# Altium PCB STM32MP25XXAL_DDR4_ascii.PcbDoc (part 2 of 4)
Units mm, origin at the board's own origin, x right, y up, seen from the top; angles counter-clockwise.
Board outline 125 x 95 mm, 6 copper layers (Top Layer, Signal Layer 1, Signal Layer 2, Signal Layer 3, Signal Layer 4, Bottom Layer), stack 1.403 mm thick; 220 components, 316 nets, 1103 pads, 939 vias.
Unrouted connection lines stored in the file: 5.

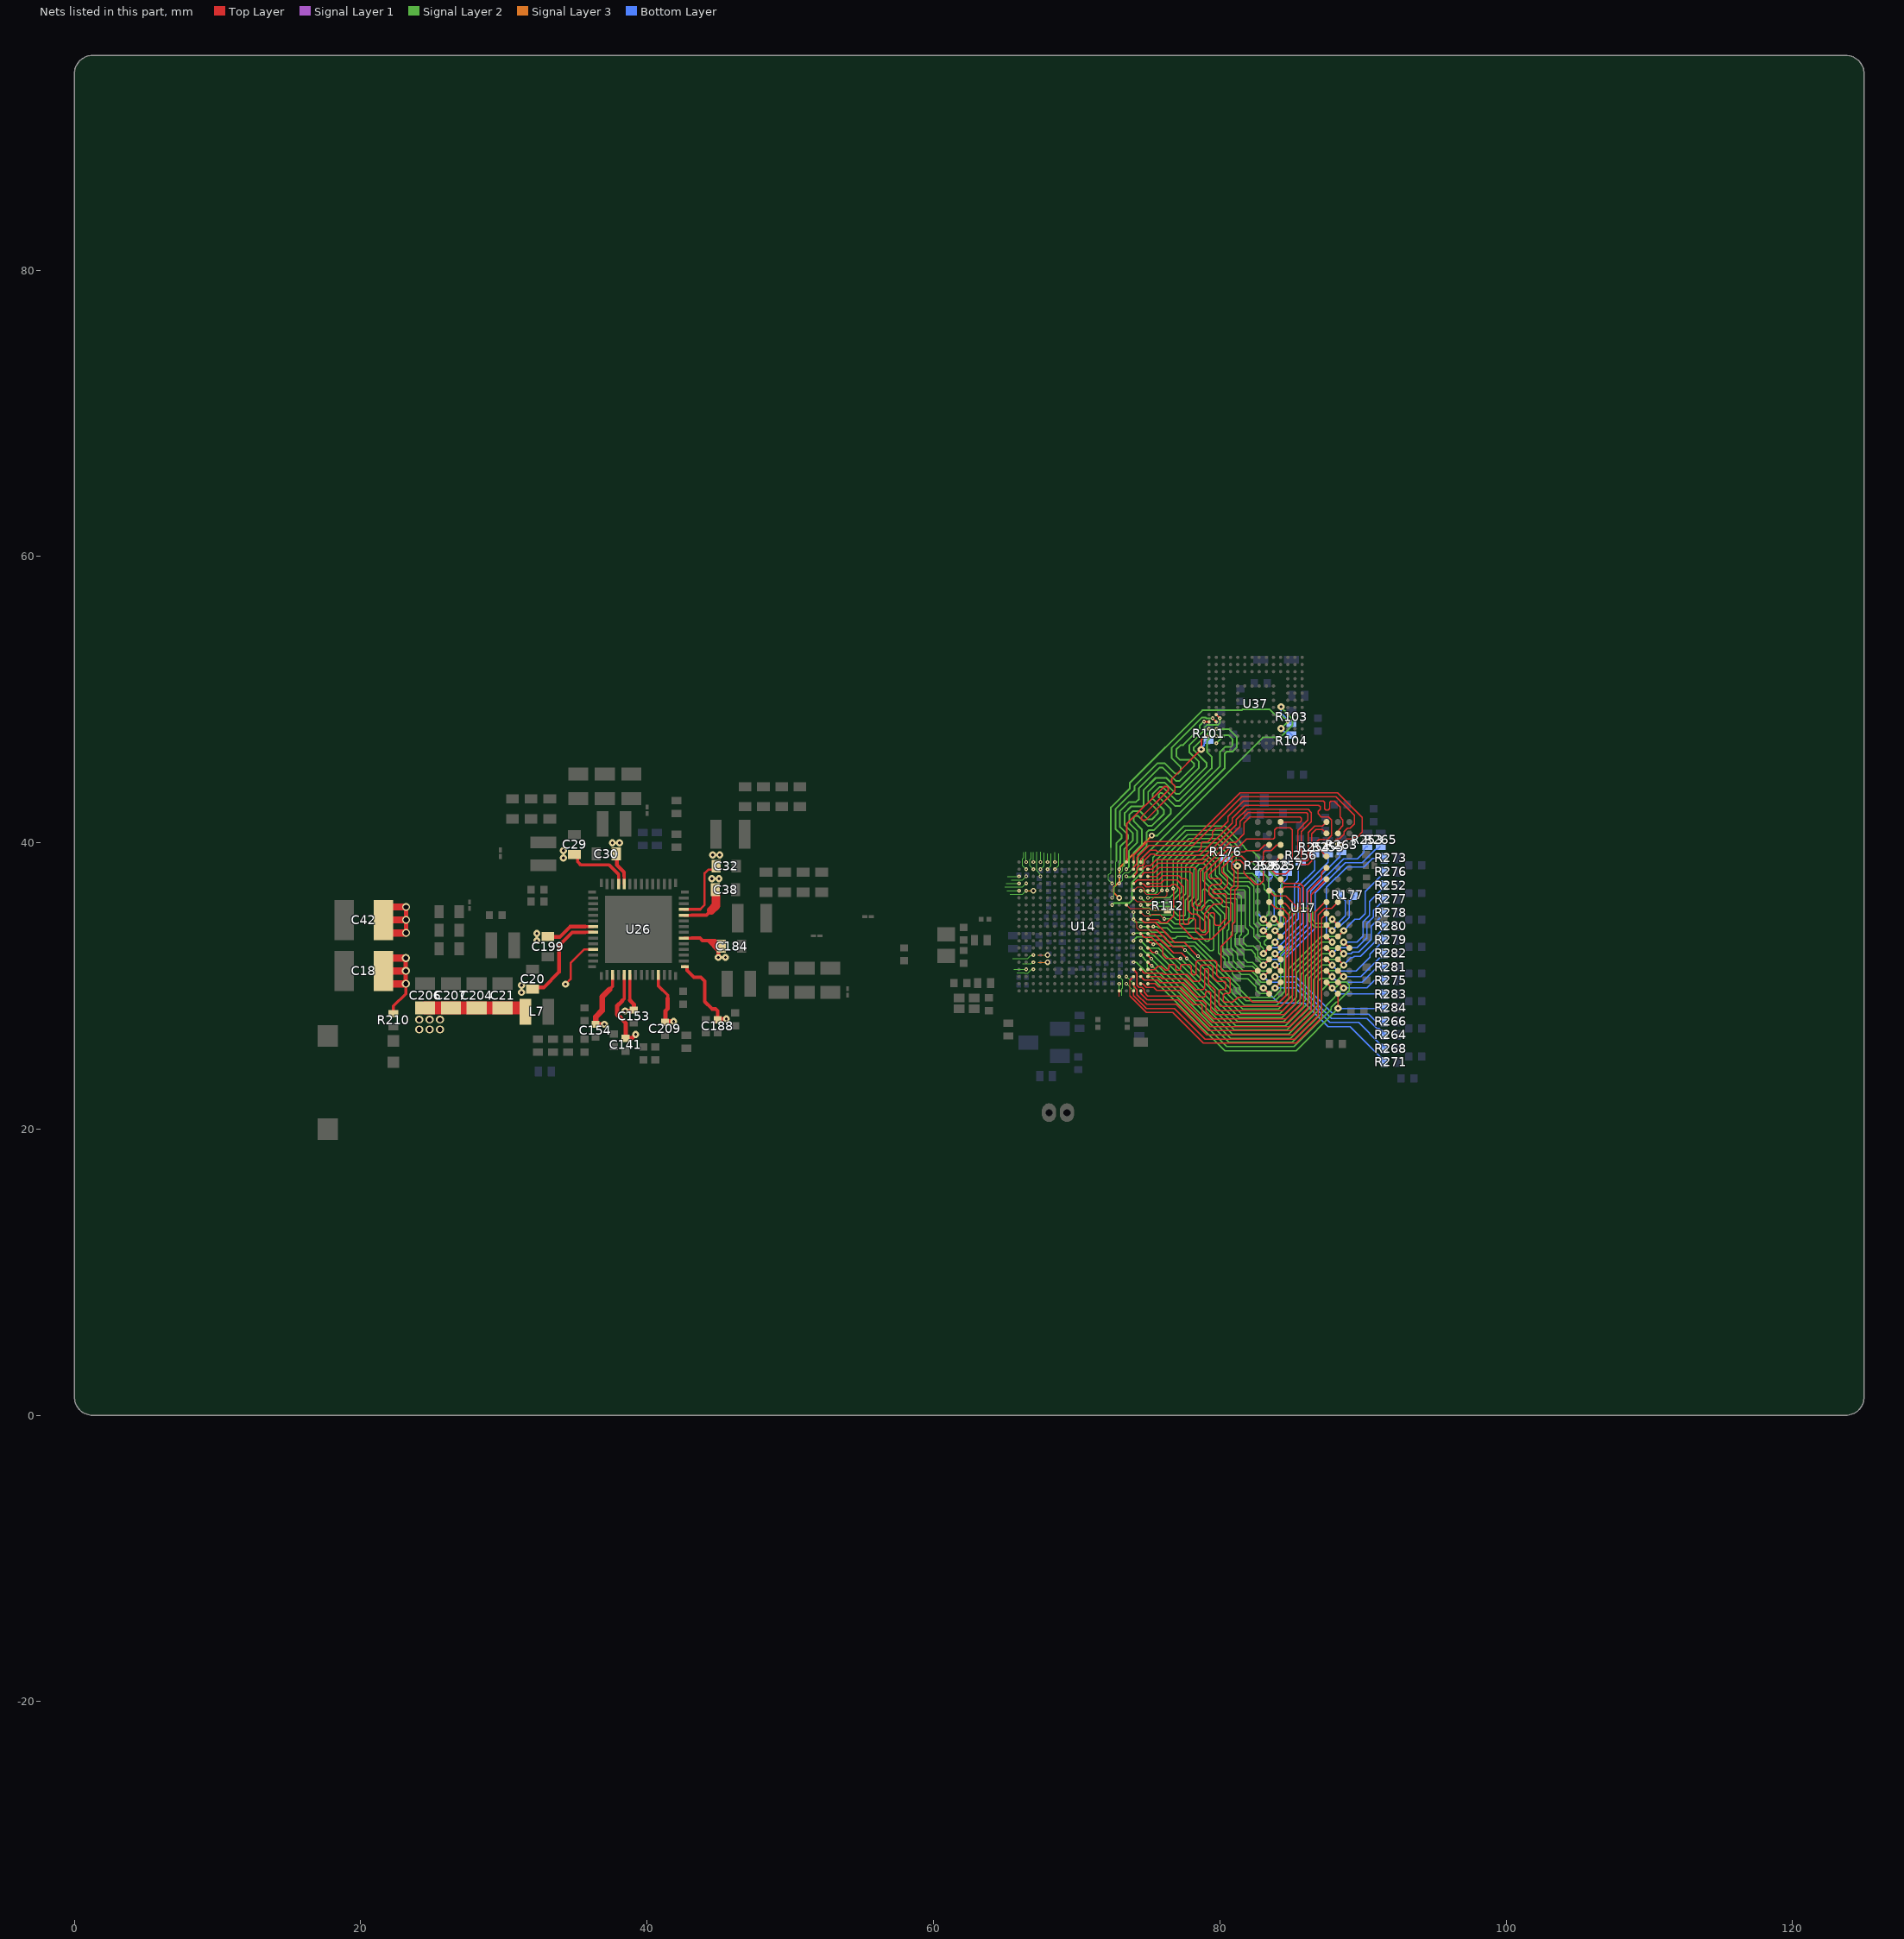
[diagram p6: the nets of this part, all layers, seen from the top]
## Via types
v1: diameter 0.5, hole 0.2, Top Layer to Bottom Layer, 292 vias
v2: diameter 0.26, hole 0.1, Top Layer to Signal Layer 1, 266 vias
v3: diameter 0.26, hole 0.1, Signal Layer 1 to Signal Layer 2, 143 vias
v4: diameter 0.4, hole 0.2, Signal Layer 1 to Signal Layer 4, 101 vias
v5: diameter 0.26, hole 0.1, Signal Layer 4 to Bottom Layer, 81 vias
v6: diameter 0.55, hole 0.35, Top Layer to Bottom Layer, 55 vias
v7: diameter 0.5, hole 0.2, Signal Layer 1 to Signal Layer 4, 1 vias

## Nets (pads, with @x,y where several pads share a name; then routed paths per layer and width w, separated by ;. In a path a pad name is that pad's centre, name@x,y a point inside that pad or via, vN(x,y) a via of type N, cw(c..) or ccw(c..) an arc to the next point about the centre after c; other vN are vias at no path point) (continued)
3V3: C21.2 C154.2 C204.2 C206.2 C207.2 L7.2 U26.3 U26.53 | length 15.3
  Top Layer w0.15: v1(34.308,30.116) 34.66,30.468 34.66,31.604 35.595,32.539 U26.53@36.228,32.539 ; U26.53@36.018,32.508 36.317,32.508 U26.53@36.348,32.539
  Top Layer w0.21: 37.371,29.736 37.598,29.964 U26.3@37.598,30.769
  Top Layer w0.3: C154.2@36.373,27.314 C154.2@36.398,27.314 v1@36.983,27.314
  Top Layer w0.4: C154.2@36.398,27.314 36.412,27.328 36.412,27.824 36.858,28.27 36.858,29.224 37.371,29.736
  Top Layer w0.9: C206.2@24.485,28.462 C21.2@29.898,28.462 31.26,28.462 L7.2@31.285,28.437
  other v1: 37.008,27.314
  other v6: 24.085,26.962 24.81,26.962 25.535,26.962 24.085,27.637 24.81,27.637 25.535,27.637
5V_STLK: C18.1 C20.2 C29.2 C30.2 C32.2 C38.2 C42.1 C153.2 C184.2 C188.2 C199.2 C209.2 R210.1 U26.6 U26.11 U26.15 U26.20 U26.24 U26.25 U26.38 U26.39 U26.49 U26.50 | length 58.9
  Top Layer w0.15: 43.698,35.339 44.023,35.664 44.023,37.87 44.286,38.133 44.717,38.133 C32.2@44.823,38.239
  Top Layer w0.2: R210.1@22.284,28.054 22.284,28.588 23.142,29.446 v6@23.142,30.133
  Top Layer w0.21: C29.2@34.923,39.189 35.16,38.952 35.16,38.652 35.373,38.439 37.362,38.439 37.998,37.803 U26.39@37.998,37.109 ; 35.673,33.739 U26.50@36.228,33.739 ; 35.673,34.139 U26.49@36.228,34.139 ; U26.38@38.398,37.109 38.398,37.664 ; 38.798,28.989 U26.6@38.798,30.769 ; U26.11@40.798,30.769 40.798,29.982 41.438,29.342 41.438,29.114 ; U26.15@42.568,31.339 U26.15@42.643,31.339 U26.15@42.683,31.339 ; U26.20@42.568,33.339 43.123,33.339 ; U26.24@42.568,34.939 43.105,34.939 ; U26.25@42.568,35.339 43.698,35.339
  Top Layer w0.25: C20.2@31.998,29.889 32.773,29.889 33.848,30.964 33.848,32.808 34.779,33.739 35.673,33.739 ; C199.2@33.073,33.414 33.889,33.414 34.614,34.139 35.673,34.139 ; C30.2@37.823,39.214 37.892,39.145 37.892,38.447 38.398,37.941 38.398,37.664 ; 42.793,31.234 42.793,31.086 43.269,30.611 43.751,30.611 44.023,30.339 44.023,28.898 44.532,28.389 44.777,28.389 44.923,28.243 C188.2@44.923,27.689 ; 43.105,34.939 44.148,34.939 44.473,35.264 ; 43.123,33.339 43.686,33.339 43.861,33.164 44.256,33.164 ; v1(44.973,31.989) 44.973,32.447 44.256,33.164 ; 44.256,33.164 44.477,33.164 ; 44.477,33.164 44.875,32.766 45.144,32.766 45.145,32.764 45.145,32.842 44.948,33.039 44.87,33.039 44.745,33.164 44.477,33.164
  Top Layer w0.3: v6@23.148,30.139 23.148,31.045 v6@23.148,31.939 ; v6@23.173,33.702 v6@23.173,35.502 ; v1(38.463,28.249) 39.073,28.249 39.072,28.25 39.072,28.715 38.798,28.989 ; C209.2@41.248,27.519 C209.2@41.273,27.519 ; 41.438,29.114 41.438,28.408 41.273,28.243 C209.2@41.273,27.519 ; v1(41.858,27.519) C209.2@41.273,27.519 ; C188.2@44.923,27.689 v1(45.533,27.689)
  Top Layer w0.5: C18.1@21.584,30.133 23.142,30.133 v6@23.167,30.133 ; C18.1@21.584,31.045 23.148,31.045 v6@23.167,31.045 ; C18.1@21.584,31.945 v6@23.167,31.945 ; C42.1@21.584,33.696 v6@23.167,33.696 ; C42.1@21.584,34.607 v6@23.167,34.607 ; C42.1@21.584,35.507 v6@23.167,35.507
  Top Layer w0.6: 44.473,35.264 44.798,35.589 C38.2@44.798,36.314
  other v1: 31.223,29.539 31.223,30.039 45.473,31.989 32.298,33.164 32.298,33.664 44.523,37.489 45.023,37.489 34.148,38.939 44.573,39.139 45.073,39.139 34.148,39.439 37.573,39.989 38.073,39.989
  other v6: 23.149,30.141 23.149,31.041 23.149,31.941 23.174,33.704 23.174,34.604 23.174,35.504
5V_VCONN: C141.1 U26.5 | length 5.7
  Top Layer w0.21: 38.276,28.966 38.398,29.089 U26.5@38.398,30.769
  Top Layer w0.3: 38.276,28.966 37.908,28.599 37.908,28.004 38.498,27.414 C141.1@38.498,26.339 38.938,26.339 v1(39.198,26.599)
ANA0: U14.R5 | length 0.7
  Signal Layer 3 w0.075: 67.3,31.65 v4(67.975,31.65)
  other v2: 67.975,31.65
ANA1: U14.P5 | length 0.7
  Signal Layer 3 w0.075: 67.275,32.15 v4(67.975,32.15)
  other v2: 67.975,32.15
BOOT0: U14.T2 | length 0.9
  Signal Layer 2 w0.075: 65.625,31.15 v3(66.475,31.15)
  other v2: 66.475,31.15
BOOT1: U14.P3 | length 1.6
  Signal Layer 2 w0.075: 65.526,31.901 66.578,31.901 66.612,31.934 66.613,31.934 66.806,32.126 66.951,32.126 v3(66.975,32.15)
  other v2: 66.975,32.15
BOOT2: U14.T3 | length 1.3
  Signal Layer 2 w0.075: 65.822,30.925 66.347,30.925 66.372,30.901 66.578,30.901 66.724,31.047 66.724,31.05 66.804,31.129 66.954,31.129 v3(66.975,31.15)
  other v2: 66.975,31.15
BOOT3: U14.R3 | length 0.8
  Signal Layer 2 w0.075: 66.221,31.558 66.839,31.558 66.931,31.65 v3(66.975,31.65)
  other v2: 66.975,31.65
COMBOPHY_REXT: U14.W15 | length 0.4
  Top Layer w0.075: 72.975,29.25 U14.W15@72.975,29.65
COMBOPHY_RX1N: U14.V16 | length 0.5
  Signal Layer 2 w0.075: v3(73.475,30.15) 73.819,29.806 73.819,29.763
  other v2: 73.475,30.15
COMBOPHY_RX1P: U14.U16 | length 1.3
  Signal Layer 2 w0.075: v3(73.475,30.65) 74.017,30.108 74.017,29.617
  other v2: 73.475,30.65
COMBOPHY_TX1N: U14.V15 | length 0.8
  Signal Layer 2 w0.075: 72.975,29.325 v3(72.975,30.15)
  other v2: 72.975,30.15
COMBOPHY_TX1P: U14.U15 | length 1.5
  Signal Layer 2 w0.075: v3(72.975,30.65) 73.224,30.401 73.224,29.874 73.15,29.8 73.15,29.325
  other v2: 72.975,30.65
CSI_CKN: U14.C2 | length 1.2
  Signal Layer 2 w0.075: 65.425,37.4 65.426,37.399 66.224,37.399 v3(66.475,37.65)
  other v2: 66.475,37.65
CSI_CKP: U14.C1 | length 0.8
  Signal Layer 2 w0.075: 65.175,37.65 65.973,37.65 v3(65.975,37.648)
  other v2: 65.975,37.648
CSI_D0N: U14.E1 | length 0.8
  Signal Layer 2 w0.075: 65.15,36.65 v3(65.975,36.65)
  other v2: 65.975,36.65
CSI_D0P: U14.E2 | length 1.2
  Signal Layer 2 w0.075: 65.35,36.4 66.225,36.4 v3(66.475,36.65)
  other v2: 66.475,36.65
CSI_D1N: U14.D2 | length 1.6
  Signal Layer 2 w0.075: 64.982,36.9 66.225,36.9 v3(66.475,37.15)
  other v2: 66.475,37.15
CSI_D1P: U14.D1 | length 0.9
  Signal Layer 2 w0.075: 65.076,37.149 v3(65.975,37.149)
  other v2: 65.975,37.149
CSI_REXT: U14.E3 | length 0.6
  Signal Layer 3 w0.075: 66.4,36.65 v2(66.975,36.65)
  other v4: 66.975,36.65
DDR_A0: R265.1 U14.H19 U17.P3 | length 31.3
  Top Layer w0.09: v1@83.855,31.445 U17.P3@84.25,31.05
  Signal Layer 2 w0.09: v3(74.975,35.15) 75.159,34.966 76.619,34.966 76.975,34.61 77.705,34.61 77.866,34.771 77.866,35.871 78.199,36.204 78.199,38.158 78.586,38.545 78.894,38.545 79.104,38.335 79.104,37.485 80.479,36.11 81.107,36.11 81.205,36.012 81.205,33.714 81.083,33.592 81.083,32.782 81.683,32.181 ; 81.683,32.18 81.683,31.891 81.924,31.65 82.291,31.65 82.891,31.05 83.446,31.05 v1@83.846,31.45
  Bottom Layer w0.09: v1@83.875,31.45 83.953,31.528 84.153,31.528 86.655,34.03 86.655,36.49 88.756,38.591 89.936,38.591 90.89,39.545 91,39.545 R265.1@91.21,39.755
  other v1: 83.85,31.45
  other v2: 74.975,35.15
DDR_A1: R281.1 U14.N18 U17.P7 | length 23.4
  Top Layer w0.09: U17.P7@87.45,31.05 v1(87.85,30.65)
  Signal Layer 2 w0.09: v3(74.475,32.65) 74.83,32.295 75.22,32.295 80.88,26.635 81.175,26.635 84.83,26.635 86.829,28.633 86.829,30.323 87.041,30.535 87.624,30.535 87.739,30.65 v1(87.85,30.65)
  Bottom Layer w0.09: v1(87.85,30.65) 88.255,30.245 89.945,30.245 90.973,31.273 91.448,31.273 R281.1@91.5,31.325
  other v2: 74.475,32.65
DDR_A2: R268.1 U14.K18 U17.R3 | length 28.8
  Top Layer w0.09: v1@83.848,29.852 84.246,30.25 U17.R3@84.25,30.25
  Signal Layer 2 w0.09: v3(74.475,34.15) 74.84,34.15 75.232,33.758 76.186,33.758 76.604,33.34 76.89,33.34 77,33.45 77.713,33.45 77.823,33.34 78.4,33.34 79.295,32.445 79.486,32.445 79.584,32.543 79.584,34.715 79.026,35.274 79.026,35.391 79.226,35.591 79.358,35.591 80.045,34.904 80.045,34.194 79.923,34.072 79.923,32.301 80.35,31.873 80.35,31.534 80.885,30.999 80.885,30.855 81.24,30.5 81.949,30.5 82.525,29.924 82.525,29.7 82.77,29.455 83.448,29.455 83.843,29.85 v1(83.85,29.85)
  Bottom Layer w0.09: v1(83.85,29.85) 85.271,29.85 87.561,27.561 87.676,27.445 89.705,27.445 91.225,25.925 91.275,25.925 91.55,25.65 R268.1@91.55,25.6
  other v2: 74.475,34.15
DDR_A3: R279.1 U14.M18 U17.N7 | length 24.1
  Top Layer w0.09: U17.N7@87.45,31.85 v1(87.85,31.45)
  Signal Layer 2 w0.09: v3(74.475,33.15) 75.002,32.623 75.715,32.623 81.122,27.215 84.588,27.215 86.249,28.876 86.249,30.563 87.135,31.45 v1(87.85,31.45)
  Bottom Layer w0.09: v1(87.85,31.45) 88.252,31.048 89.532,31.048 90.477,31.993 90.477,32.202 91.19,32.915 91.275,32.915 91.525,33.165 R279.1@91.525,33.25
  other v2: 74.475,33.15
DDR_A4: R263.1 U14.G19 U17.N3 | length 28
  Top Layer w0.09: U14.G19@74.975,35.65 74.979,35.646 75.387,35.646 v2@75.508,35.525 ; v1(83.85,32.25) 83.85,32.246 U17.N3@84.253,31.843
  Signal Layer 2 w0.09: v3@75.623,35.548 76.856,35.548 76.93,35.475 77.2,35.475 77.286,35.561 77.286,36.111 77.619,36.445 77.619,38.398 78.346,39.125 79.135,39.125 79.684,38.576 79.684,37.726 80.72,36.69 81.676,36.69 81.785,36.581 81.785,34.08 81.983,33.882 81.983,33.672 81.663,33.351 81.663,33.024 81.894,32.793 82.357,32.793 82.653,32.497 82.653,32.096 ; 82.655,32.094 82.9,31.85 83.45,31.85 ; 83.455,31.855 v1(83.85,32.25)
  Bottom Layer w0.09: v1@83.784,32.192 v1@83.846,32.254 ; v1(83.85,32.25) 83.928,32.328 84.133,32.328 86.075,34.27 86.075,36.73 88.382,39.038 88.382,39.232 R263.1@88.525,39.375
  other v2: 75.525,35.531
  other v3: 75.525,35.531
DDR_A5: R282.1 U14.P19 U17.P8 | length 22.8
  Top Layer w0.09: U14.P19@74.975,32.15 v2@75.275,31.85 ; U17.P8@88.25,31.05 v1(88.65,30.65)
  Signal Layer 2 w0.09: v3@75.21,31.885 80.75,26.345 80.931,26.345 84.95,26.345 87.119,28.513 87.119,29.687 87.682,30.25 88.072,30.25 88.393,30.572 88.572,30.572 v1(88.65,30.65)
  Bottom Layer w0.09: v1(88.65,30.65) 89.85,30.65 91.17,31.97 91.275,31.97 91.5,32.195 R282.1@91.5,32.3
  other v2: 75.22,31.895
  other v3: 75.22,31.895
DDR_A6: R264.1 U14.H18 U17.P2 | length 28.9
  Top Layer w0.075: U14.H18@74.475,35.15 74.725,34.9 75.175,34.9 75.3,35.025 75.781,35.025 v3(76.125,34.682)
  Top Layer w0.09: v1(83.05,30.65) U17.P2@83.45,31.05
  Signal Layer 2 w0.09: v3@76.131,34.676 76.498,34.676 76.854,34.32 77.825,34.32 78.156,34.651 78.156,35.751 78.489,36.084 78.489,38.038 78.624,38.173 78.739,38.173 78.814,38.097 78.814,37.365 80.359,35.82 80.795,35.82 80.915,35.7 80.915,33.834 80.793,33.712 80.793,32.662 81.221,32.233 81.221,31.894 81.745,31.37 82.282,31.37 v1@83.042,30.61 ; v1@83.042,30.65 v1(83.05,30.65)
  Bottom Layer w0.09: v1(83.05,30.65) 83.455,30.245 85.286,30.245 87.603,27.928 87.796,27.735 90.28,27.735 90.98,27.035 91.123,27.035 91.275,26.883 91.275,26.825 R264.1@91.525,26.575
  other v2: 76.125,34.682
DDR_A7: R275.1 U14.R19 U17.R8 | length 21.2
  Top Layer w0.09: U14.R19@74.975,31.65 v2@75.2,31.425 ; U17.R8@88.25,30.25 v1(88.65,29.85)
  Signal Layer 2 w0.09: v3(75.25,31.4) 75.275,31.4 80.62,26.055 85.07,26.055 87.409,28.393 87.409,28.609 v1(88.65,29.85)
  Bottom Layer w0.09: v1(88.65,29.85) 90.275,29.85 90.8,30.375 R275.1@91.475,30.375
  other v2: 75.25,31.4
DDR_A8: R266.1 U14.H17 U17.R2 | length 28.9
  Top Layer w0.09: U17.R2@83.45,30.25 v1(83.85,30.65)
  Signal Layer 2 w0.09: v3(73.975,35.15) 73.975,34.55 74.085,34.44 75.723,34.44 75.825,34.338 76.426,34.338 76.734,34.03 78.53,34.03 78.816,33.744 78.933,33.744 79.004,33.815 79.004,34.471 78.446,35.029 78.446,35.631 78.779,35.964 78.779,36.679 78.875,36.775 78.994,36.775 80.239,35.53 80.522,35.53 80.625,35.427 80.625,33.954 80.503,33.832 80.503,32.541 80.931,32.113 80.931,31.773 81.625,31.08 82.205,31.08 82.655,30.63 82.655,30.48 82.88,30.255 83.48,30.255 v1@83.875,30.65
  Bottom Layer w0.09: v1(83.85,30.65) 85.291,30.65 87.916,28.025 90.4,28.025 90.9,27.525 R266.1@91.55,27.525
  other v2: 73.975,35.15
DDR_A9: R283.1 U14.P18 U17.R7 | length 25.4
  Top Layer w0.09: U17.R7@87.45,30.25 v1(87.85,29.85)
  Signal Layer 2 w0.09: v3@74.475,32.144 74.935,31.684 74.935,31.305 80.475,25.765 85.191,25.765 87.775,28.349 87.775,28.509 88.141,28.875 88.239,28.875 89.045,29.681 89.045,30.055 88.85,30.25 88.491,30.25 88.15,29.909 87.909,29.909 v1(87.85,29.85)
  Bottom Layer w0.09: v1(87.85,29.85) 88.275,29.425 R283.1@91.525,29.425
  other v2: 74.475,32.15
  other v3: 74.475,32.15
DDR_A10: R254.1 U14.F19 U17.M3 | length 25.6
  Top Layer w0.09: v1@83.85,33.049 U17.M3@84.25,32.65
  Signal Layer 2 w0.09: v3@74.974,36.15 76.504,36.15 77.039,36.685 77.039,38.638 78.106,39.705 79.68,39.705 79.768,39.616 79.768,39.312 79.86,39.219 80.165,39.219 80.264,39.121 80.264,37.966 80.96,37.27 82.053,37.27 82.365,36.958 82.365,34.366 82.655,34.076 82.655,33.58 82.785,33.45 83.2,33.45 83.275,33.375 83.275,33.253 83.114,33.093 83.114,32.946 83.364,32.696 83.496,32.696 v1(83.85,33.05)
  Bottom Layer w0.09: v1(83.85,33.05) 85.495,34.695 85.495,36.971 86.625,38.1 86.625,39.2 R254.1@86.6,39.225
  other v2: 74.975,36.15
  other v3: 74.975,36.15
DDR_A11: R271.1 U14.K19 U17.T2 | length 27.5
  Top Layer w0.075: U14.K19@74.975,34.15 v2(75.35,34.15)
  Top Layer w0.09: v1@83.071,29.84 83.45,29.461 U17.T2@83.45,29.45
  Signal Layer 2 w0.09: v2(75.35,34.15) 75.603,34.15 75.705,34.048 76.306,34.048 76.614,33.74 78.41,33.74 79.024,33.126 79.189,33.126 79.294,33.231 79.294,34.595 78.736,35.153 78.736,35.511 79.213,35.988 79.371,35.988 80.335,35.024 80.335,34.074 80.213,33.952 80.213,32.421 80.64,31.994 80.64,31.654 81.505,30.79 82.069,30.79 83.025,29.834 v1@83.025,29.8 ; v1@83.025,29.85 v1(83.05,29.85)
  Bottom Layer w0.09: v1(83.05,29.85) 84.1,28.8 85.911,28.8 87.556,27.155 89.109,27.155 91.275,24.99 91.275,24.9 R271.1@91.5,24.675
  other v3: 75.35,34.15
DDR_A12: R277.1 U14.L18 U17.M7 | length 25.6
  Top Layer w0.09: U14.L18@74.475,33.65 74.725,33.4 75.241,33.4 76.025,32.616 ; 76.025,32.625 76.025,32.616 ; v3(77.255,31.917) 76.258,31.917 76.025,32.15 76.025,32.616 ; U17.M7@87.45,32.65 v1(87.85,32.25)
  Signal Layer 2 w0.09: v3(77.255,31.917) 77.255,31.902 81.362,27.795 84.348,27.795 85.669,29.116 85.669,30.804 87.115,32.25 v1(87.85,32.25)
  Bottom Layer w0.09: v1@87.85,32.25 88.255,32.655 89.59,32.655 90.29,33.355 90.29,34.341 90.74,34.792 90.74,35.265 91.24,35.765 91.275,35.765 91.525,36.015 R277.1@91.525,36.05
  other v2: 77.255,31.917
DDR_A13: R284.1 U14.R17 U17.T8 | length 22.4
  Top Layer w0.09: v1(88.25,28.425) U17.T8@88.25,29.45
  Signal Layer 2 w0.09: v3@73.925,31.65 v3(73.975,31.65) 74.18,31.65 80.355,25.475 85.325,25.475 88.25,28.4 v1(88.25,28.425)
  Bottom Layer w0.09: v1(88.25,28.425) 91.5,28.425 R284.1@91.525,28.45
  other v2: 73.975,31.65
DDR_ACTN: R256.1 U14.E19 U17.L3 | length 24.4
  Top Layer w0.09: U14.E19@74.975,36.65 75,36.675 v2(75.325,36.675) ; v1(83.85,33.85) U17.L3@84.25,33.45
  Signal Layer 2 w0.09: v3@75.325,36.65 75.325,38.975 77.505,41.155 80.35,41.155 81.427,40.077 81.427,40.008 81.714,39.721 81.714,39.668 81.931,39.45 82.259,39.45 82.75,38.959 82.75,38.775 ; 82.757,38.761 84.325,37.193 84.325,35.57 84.468,35.427 84.468,34.403 83.915,33.85 v1(83.85,33.85)
  Bottom Layer w0.09: v1(83.85,33.85) 83.961,33.85 84.071,33.96 84.136,33.96 85.205,35.029 85.205,37.091 85.47,37.355 85.47,38.52 R256.1@85.65,38.7
  other v3: 75.325,36.675
DDR_BA0: R253.1 U14.G18 U17.N2 | length 30.9
  Top Layer w0.09: v1@83.052,31.447 83.45,31.845 U17.N2@83.45,31.85
  Signal Layer 2 w0.09: v3(74.475,35.65) 74.685,35.44 75.095,35.44 75.279,35.256 76.739,35.256 77.095,34.9 77.523,34.9 77.576,34.953 77.576,35.991 77.909,36.324 77.909,38.278 78.466,38.835 79.014,38.835 79.394,38.456 79.394,37.606 80.599,36.4 81.335,36.4 81.495,36.24 81.495,33.594 81.373,33.471 81.373,32.902 81.772,32.503 82.189,32.503 82.473,32.219 82.473,32.022 83.045,31.45 v1(83.05,31.45)
  Bottom Layer w0.09: v1(83.05,31.45) 83.455,31.855 84.07,31.855 86.365,34.15 86.365,36.61 88.635,38.881 89.604,38.881 90.051,39.328 90.051,39.545 90.231,39.725 R253.1@90.325,39.725
  other v2: 74.475,35.65
DDR_BA1: R280.1 U14.N19 U17.N8 | length 23.7
  Top Layer w0.09: U14.N19@74.975,32.65 74.989,32.65 75.296,32.343 v2(75.584,32.343) ; U17.N8@88.25,31.85 v1(88.65,31.45) v1@88.62,31.45
  Signal Layer 2 w0.09: v2(75.584,32.343) 81.002,26.925 84.71,26.925 86.539,28.753 86.539,30.443 87.148,31.053 88.253,31.053 v1(88.65,31.45)
  Bottom Layer w0.09: v1(88.65,31.45) 89.16,31.96 89.295,31.96 89.41,32.075 89.83,32.075 90.87,33.115 90.87,33.46 91.525,34.115 R280.1@91.525,34.175
  other v3: 75.584,32.343
DDR_BG0: R255.1 U14.F18 U17.M2 | length 26.9
  Top Layer w0.09: v1@83.058,32.258 83.058,32.27 83.438,32.65 U17.M2@83.45,32.65
  Signal Layer 2 w0.09: v3(74.475,36.15) 74.895,35.73 75.195,35.73 75.303,35.838 76.603,35.838 77.329,36.565 77.329,38.518 78.226,39.415 79.255,39.415 79.74,38.929 79.87,38.929 79.974,38.826 79.974,37.846 80.84,36.98 81.932,36.98 82.075,36.837 82.075,34.246 82.365,33.956 82.365,33.46 82.824,33.001 82.824,32.826 83.05,32.6 v1(83.05,32.258) v1@83.05,32.225
  Bottom Layer w0.09: v1(83.05,32.258) 83.448,32.655 84.05,32.655 85.785,34.39 85.785,36.85 87.575,38.64 R255.1@87.575,39.225
  other v2: 74.475,36.15
DDR_BG1: R252.1 U14.L19 U17.M9 | length 25.3
  Top Layer w0.09: U14.L19@74.981,33.644 75.426,33.644 76.764,32.306 77.319,32.306 v2@77.7,31.925 ; v1(88.65,33.05) U17.M9@89.05,32.65
  Signal Layer 2 w0.09: v2(77.695,31.92) 80.27,29.345 80.27,29.298 81.482,28.085 84.228,28.085 85.379,29.236 85.379,30.924 87.103,32.648 88.248,32.648 v1(88.65,33.05)
  Bottom Layer w0.09: v1(88.65,33.05) 89.575,33.05 90,33.475 90,34.461 90.45,34.912 90.45,35.89 91.5,36.94 R252.1@91.5,37.025
  other v3: 77.695,31.92
DDR_CASN: R278.1 U14.M19 U17.M8 | length 24.2
  Top Layer w0.09: U14.M19@74.975,33.15 75.102,33.023 75.212,33.023 75.335,32.9 v3(75.35,32.9) ; U17.M8@88.25,32.65 v1(88.65,32.25)
  Signal Layer 2 w0.09: v3(75.35,32.9) 75.373,32.923 75.824,32.923 81.242,27.505 84.468,27.505 85.959,28.996 85.959,30.683 87.125,31.85 88.25,31.85 v1(88.65,32.25)
  Bottom Layer w0.09: v1(88.65,32.25) 89.175,32.25 89.29,32.365 89.71,32.365 90.58,33.235 90.58,34.162 91.233,34.815 91.275,34.815 91.5,35.04 R278.1@91.5,35.1
  other v2: 75.35,32.9
DDR_CKE: R259.1 U14.F17 U17.K2 | length 21.2
  Top Layer w0.075: U14.F17@73.975,36.15 73.975,36.139 74.214,35.901 75.146,35.901 75.471,36.226 76.201,36.226 76.325,36.35 v3(76.325,36.675)
  Top Layer w0.09: v1@83.057,34.64 83.447,34.25 U17.K2@83.45,34.25
  Signal Layer 2 w0.09: v3(76.325,36.675) 76.325,38.745 77.865,40.285 79.92,40.285 80.844,39.361 80.844,38.206 81.2,37.85 82.293,37.85 83.1,37.043 83.1,36.759 83.445,36.414 83.445,35.045 v1(83.05,34.65)
  Bottom Layer w0.09: R259.1@82.825,37.925 82.733,37.833 82.733,37.608 82.655,37.53 82.655,35.045 v1(83.05,34.65)
  other v2: 76.325,36.675
DDR_CLK_N: R177.2 U14.L17 U17.K8 | length 25.5
  Top Layer w0.09: v1(87.85,34.65) U17.K8@88.25,34.25
  Signal Layer 2 w0.09: v3(73.975,33.65) 74.006,33.681 74.897,33.681 75.11,33.468 76.066,33.468 76.484,33.05 78.28,33.05 81.39,29.94 81.39,29.761 81.946,29.205 83.764,29.205 84.259,29.7 84.259,32.209 84.849,32.799 84.849,35.099 85.175,35.425 86.175,35.425 86.475,35.125 86.475,34.625 86.734,34.366 87.664,34.366 87.85,34.551 v1(87.85,34.65)
  Bottom Layer w0.09: v1(87.85,34.65) 88.086,34.414 88.301,34.414 88.78,34.893 88.78,35.948 88.683,36.045 88.68,36.045 88.47,36.255 R177.2@88.47,36.35
  other v2: 73.975,33.65
DDR_CLK_P: R177.1 U14.M17 U17.K7 | length 26
  Top Layer w0.09: U17.K7@87.45,34.25 v1(87.85,33.85)
  Signal Layer 2 w0.09: v2(73.975,33.15) 73.975,33.196 74.211,33.431 74.794,33.431 75.007,33.218 75.962,33.218 76.38,32.8 78.176,32.8 81.14,29.836 81.14,29.658 81.843,28.955 83.867,28.955 84.509,29.596 84.509,32.105 85.099,32.696 85.099,34.996 85.279,35.175 86.071,35.175 86.225,35.021 86.225,34.521 86.631,34.116 87.646,34.116 v1@87.825,33.936
  Bottom Layer w0.09: v1(87.85,33.85) 88.05,34.05 88.164,34.164 88.405,34.164 89.03,34.79 89.03,35.916 89.159,36.045 89.37,36.255 R177.1@89.37,36.35
  other v3: 73.975,33.15
DDR_CSN: R273.1 U14.J17 U17.L7 | length 29.2
  Top Layer w0.075: v2(73.975,34.65) 74.217,34.408 74.217,34.045 74.369,33.894 ; 74.375,33.893 75.4,33.893
  Top Layer w0.09: 75.4,33.893 75.587,33.893 76.755,32.725 77.35,32.725 v3(77.575,32.5) v2@77.575,32.525 ; U17.L7@87.45,33.45 v1(87.85,33.05)
  Signal Layer 2 w0.09: v3(77.575,32.5) 80.56,29.515 80.56,29.418 81.603,28.375 84.107,28.375 85.089,29.356 85.089,31.044 87.095,33.05 v1(87.85,33.05)
  Bottom Layer w0.09: v1(87.85,33.05) 87.455,33.445 87.455,36.88 88.876,38.301 90.056,38.301 90.655,38.9 R273.1@91.525,38.9
  other v2: 77.575,32.5
DDR_DQ0: U14.W18 U17.F7 | length 23.3
  Top Layer w0.09: U14.W18@74.48,29.645 74.486,29.639 74.486,29.475 74.948,29.012 ; 74.951,29.014 74.955,29.01 77.074,29.01 79.219,26.865 84.967,26.865 86.385,28.283 86.385,36.378 U17.F7@87.453,37.446
DDR_DQ1: U14.W17 U17.H8 | length 23.9
  Top Layer w0.09: U14.W17@73.975,29.65 73.975,29.322 74.872,28.425 76.839,28.425 78.979,26.285 85.207,26.285 86.865,27.943 86.865,34.953 87.331,35.419 87.819,35.419 U17.H8@88.25,35.85
DDR_DQ2: U14.V17 U17.H7 | length 23.2
  Top Layer w0.09: U14.V17@73.975,30.15 73.989,30.136 73.989,29.99 74.225,29.754 74.225,29.384 74.89,28.719 ; 74.89,28.72 76.954,28.72 79.099,26.575 85.087,26.575 86.625,28.113 86.625,35.123 87.352,35.85 U17.H7@87.45,35.85
DDR_DQ3: U14.U17 U17.J7 | length 24.4
  Top Layer w0.075: 73.725,29.275 73.725,30.4
  Top Layer w0.09: 73.725,29.275 74.861,28.139 ; 73.725,30.4 U14.U17@73.975,30.65 ; 74.875,28.135 76.719,28.135 78.859,25.995 85.328,25.995 87.105,27.772 87.105,34.705 U17.J7@87.45,35.05
DDR_DQ4: U14.T19 U17.J3 | length 22
  Top Layer w0.09: U14.T19@74.975,31.15 74.993,31.132 75.432,31.132 75.683,31.383 75.911,31.383 76.21,31.084 ; 76.21,31.085 76.361,31.085 76.45,31.174 76.45,31.396 76.535,31.481 76.819,31.481 76.925,31.375 76.925,31.17 77.01,31.085 77.175,31.085 77.25,31.16 77.25,31.377 77.354,31.481 77.886,31.481 78,31.368 78,30.898 78.141,30.757 78.26,30.757 78.35,30.847 78.35,31.641 78.466,31.757 79.675,31.757 79.8,31.631 79.8,30.725 79.925,30.6 80.602,30.6 80.724,30.478 80.724,29.56 80.628,29.464 80.351,29.464 80.238,29.351 80.238,28.951 80.334,28.855 80.905,28.855 81.255,29.205 81.945,29.205 82.295,28.855 84.143,28.855 84.595,29.307 84.595,34.705 U17.J3@84.25,35.05
DDR_DQ5: U14.T18 U17.H2 | length 22.9
  Top Layer w0.09: U14.T18@74.475,31.15 74.725,30.9 75.979,30.9 76.084,30.795 77.693,30.795 78.163,30.325 78.553,30.325 78.64,30.412 78.64,31.346 78.761,31.467 79.374,31.467 79.51,31.33 79.51,30.605 79.805,30.31 80.334,30.31 80.434,30.21 80.434,29.868 80.32,29.754 80.046,29.754 79.948,29.655 79.948,28.69 80.072,28.565 84.263,28.565 84.835,29.137 84.835,34.953 84.393,35.395 83.905,35.395 U17.H2@83.45,35.85
DDR_DQ6: U14.U19 U17.H3 | length 21.9
  Top Layer w0.09: U14.U19@74.975,30.65 75.809,30.65 75.812,30.65 75.951,30.511 ; 75.957,30.505 77.573,30.505 78.338,29.74 78.81,29.74 78.93,29.86 78.93,31.11 78.996,31.177 79.143,31.177 79.22,31.099 79.22,30.144 79.658,29.707 79.658,28.45 79.832,28.275 84.383,28.275 85.075,28.967 85.075,35.23 84.54,35.765 84.335,35.765 U17.H3@84.25,35.85
DDR_DQ7: U14.U18 U17.G2 | length 22.5
  Top Layer w0.09: U14.U18@74.475,30.65 74.725,30.4 75.659,30.4 ; 75.659,30.4 75.845,30.215 77.453,30.215 78.428,29.24 78.925,29.24 79.003,29.319 79.003,29.523 79.095,29.614 79.254,29.614 79.368,29.501 79.368,28.329 79.712,27.985 84.503,27.985 85.315,28.797 85.315,35.579 84.601,36.293 83.803,36.293 U17.G2@83.453,36.643
DDR_DQ8: U14.C17 U17.D7 | length 21
  Top Layer w0.09: U14.C17@73.975,37.65 74.225,37.9 74.225,38.254 74.371,38.4 74.579,38.4 74.725,38.546 74.725,38.754 75.168,39.196 75.406,39.196 75.5,39.103 78.595,39.103 80.865,41.373 80.865,41.722 81.768,42.625 86.908,42.625 87.012,42.522 87.012,42.338 ; 87.012,42.337 86.86,42.185 86.86,42.031 87.096,41.795 87.593,41.795 87.795,41.593 87.795,40.489 87.538,40.233 86.937,40.233 86.819,40.114 86.819,39.681 U17.D7@87.45,39.05
DDR_DQ9: U14.A18 U17.B8 | length 19.8
  Top Layer w0.09: U14.A18@74.484,38.65 74.484,38.85 ; 74.485,38.851 75.12,39.486 75.526,39.486 75.62,39.393 78.475,39.393 78.699,39.617 78.699,39.967 78.794,40.062 79.144,40.062 79.487,40.405 79.487,40.755 79.732,41 80.082,41 80.575,41.493 80.575,41.843 81.647,42.915 87.232,42.915 87.325,42.822 87.325,42.36 87.406,42.279 87.567,42.279 87.692,42.405 87.692,42.823 87.784,42.915 87.981,42.915 88.145,42.75 88.395,42.501 88.395,41.793 88.595,41.593 88.595,41.197 88.303,40.905 88.303,40.703 U17.B8@88.25,40.65
DDR_DQ10: U14.B17 U17.C7 | length 21.6
  Top Layer w0.09: U14.B17@73.975,38.15 73.975,38.285 74.225,38.535 74.225,38.975 75.044,39.794 78.116,39.794 81.527,43.205 88.1,43.205 ; U17.C7@87.45,39.85 87.454,39.854 87.742,39.854 88.134,40.246 88.343,40.246 88.678,40.581 88.678,40.768 88.929,41.019 89.106,41.019 89.395,41.307 89.395,41.912 88.107,43.2 88.1,43.2
DDR_DQ11: U14.A17 U17.C8 | length 22.1
  Top Layer w0.09: U14.A17@73.975,38.65 73.975,39.1 73.975,39.11 74.949,40.084 77.996,40.084 81.407,43.495 88.222,43.495 89.955,41.762 89.955,40.741 89.609,40.395 89.39,40.395 89.252,40.257 88.898,40.257 88.541,39.9 88.3,39.9 U17.C8@88.25,39.85
DDR_DQ12: U14.D19 U17.C3 | length 22.5
  Top Layer w0.09: U14.D19@74.975,37.15 75.875,37.15 76.124,37.399 77.002,37.399 77.476,36.925 77.476,34.408 77.578,34.306 77.731,34.306 77.825,34.4 77.825,34.625 77.912,34.712 78.213,34.712 78.325,34.6 78.325,33.84 78.604,33.561 78.966,33.561 79.224,33.819 79.224,34.941 79.389,35.106 79.55,35.106 79.648,35.008 79.648,34.322 79.732,34.238 79.987,34.238 80.465,34.716 80.465,36.322 80.362,36.425 79.625,36.425 79.522,36.527 79.522,36.672 79.626,36.776 80.264,36.776 80.55,37.062 80.55,37.55 80.15,37.95 80.15,38.254 80.956,39.06 81.531,39.06 81.94,38.652 82.862,38.652 83.047,38.837 83.047,39.34 83.151,39.443 83.59,39.443 83.977,39.83 84.239,39.83 U17.C3@84.253,39.843
DDR_DQ13: U14.D18 U17.D3 | length 20.2
  Top Layer w0.09: U14.D18@74.475,37.15 74.502,37.123 74.648,37.123 74.871,36.9 ; 74.875,36.9 75.079,36.9 75.129,36.95 76.511,36.95 76.67,37.109 76.882,37.109 77.186,36.805 77.186,34.288 78.202,33.271 79.43,33.271 80.755,34.596 80.755,36.786 80.986,37.017 80.986,38.07 80.845,38.211 80.845,38.539 81.076,38.77 81.411,38.77 81.678,38.503 81.678,37.878 82.455,37.1 ; 82.455,37.105 82.793,37.105 83.037,37.349 83.037,38.417 83.294,38.674 83.883,38.674 U17.D3@84.253,39.043
DDR_DQ14: U14.D17 U17.C2 | length 20.3
  Top Layer w0.09: U14.D17@73.994,37.164 74.23,37.4 75.741,37.4 76.03,37.689 77.122,37.689 77.327,37.484 77.623,37.484 77.771,37.337 77.771,35.278 78.039,35.01 78.375,35.01 78.625,34.76 78.625,33.95 78.724,33.851 78.842,33.851 78.876,33.885 78.88,33.885 78.933,33.938 78.933,35.06 79.573,35.7 80.032,35.7 80.175,35.843 80.175,35.983 80.023,36.135 79.505,36.135 79.232,36.407 79.232,36.852 79.447,37.066 80.006,37.066 80.132,37.192 80.132,37.363 80.009,37.486 79.341,37.486 79.232,37.595 79.232,37.746 80.836,39.35 81.726,39.35 81.83,39.454 82.751,39.454 83.141,39.843 U17.C2@83.453,39.843
DDR_DQ15: U14.C18 U17.A3 | length 20.1
  Top Layer w0.09: U14.C18@74.48,37.65 74.73,37.9 75.421,37.9 75.791,38.269 77.975,38.269 78.231,38.269 78.351,38.149 78.351,35.702 78.458,35.595 78.576,35.595 78.652,35.671 78.652,37.987 80.691,40.025 81.11,40.025 81.695,40.61 81.695,40.975 81.695,41.379 82.111,41.795 85.595,41.795 85.692,41.699 85.692,41.526 85.616,41.45 U17.A3@84.25,41.45
DDR_DQM0: U14.T17 U17.E7 | length 25.3
  Top Layer w0.09: U14.T17@73.975,31.15 74.225,30.9 74.225,30.046 74.371,29.9 74.579,29.9 74.725,29.754 74.725,29.546 74.971,29.3 77.194,29.3 79.339,27.155 84.847,27.155 86.145,28.453 86.145,36.548 87.105,37.508 87.105,37.905 U17.E7@87.45,38.25
DDR_DQM1: U14.C19 U17.E2 | length 21.4
  Top Layer w0.09: U14.C19@74.978,37.647 75.578,37.647 75.911,37.98 77.93,37.979 78.061,37.849 78.061,35.582 78.343,35.3 78.692,35.3 78.942,35.551 78.942,37.866 80.811,39.735 81.362,39.735 81.876,40.249 ; 81.877,40.248 83.749,40.248 83.841,40.341 83.841,40.901 83.975,41.034 84.897,41.034 85.05,40.881 85.05,38.256 84.601,37.808 83.899,37.808 U17.E2@83.457,38.25
DDR_DQS0_N: U14.V18 U17.F3 | length 23.4
  Top Layer w0.09: U14.V18@74.485,30.145 74.626,30.145 74.871,29.9 75.375,29.9 75.6,29.675 ; 75.596,29.675 75.6,29.675 ; U17.F3@84.253,37.443 84.529,37.167 85.596,37.167 85.855,36.908 85.855,28.573 84.727,27.445 79.459,27.445 78.775,28.129 78.775,28.627 78.702,28.7 78.204,28.7 77.229,29.675 75.6,29.675
DDR_DQS0_P: U14.V19 U17.G3 | length 22
  Top Layer w0.09: U14.V19@74.975,30.15 75.04,30.15 75.479,30.15 75.704,29.925 77.333,29.925 78.308,28.95 78.806,28.95 79.025,28.731 79.025,28.233 79.563,27.695 84.623,27.695 85.605,28.677 85.605,36.805 85.492,36.917 84.517,36.917 U17.G3@84.25,36.65
DDR_DQS1_N: U14.B18 U17.A7 | length 21.5
  Top Layer w0.09: U14.B18@74.475,38.15 74.494,38.169 74.629,38.169 74.86,38.4 75.157,38.4 75.57,38.813 78.715,38.813 81.155,41.253 81.155,41.602 81.888,42.335 86.169,42.335 86.4,42.104 86.4,41.47 85.694,40.764 85.694,38.859 85.829,38.725 86.071,38.725 86.173,38.827 86.173,40.716 86.616,41.159 87.169,41.159 U17.A7@87.453,41.443
DDR_DQS1_P: U14.B19 U17.B7 | length 20.9
  Top Layer w0.09: U14.B19@74.975,38.15 75.26,38.15 75.673,38.563 78.818,38.563 81.405,41.149 81.405,41.499 81.991,42.085 86.065,42.085 86.15,42 ; 86.149,42 86.149,41.572 85.444,40.868 85.444,38.756 85.725,38.475 86.175,38.475 86.423,38.723 86.423,40.613 86.72,40.909 87.173,40.909 U17.B7@87.451,40.631
DDR_ODT: R258.1 U14.J19 U17.K3 | length 22.4
  Top Layer w0.09: U14.J19@74.975,34.65 74.994,34.631 75.694,34.631 75.9,34.425 76.3,34.425 76.766,34.891 76.766,36.784 v2(76.75,36.8) ; v1(83.783,34.687) 83.822,34.648 83.848,34.648 U17.K3@84.253,34.243
  Signal Layer 1 w0.1: v3@76.749,36.861 76.764,36.846 76.764,36.82 v3@76.77,36.815
  Signal Layer 2 w0.09: v3@76.749,36.861 76.749,38.758 77.985,39.995 79.8,39.995 80.554,39.241 80.554,38.086 81.08,37.56 82.173,37.56 82.655,37.078 82.655,34.486 82.896,34.245 83.233,34.245 83.675,34.687 v1(83.783,34.687)
  Bottom Layer w0.09: R258.1@83.75,37.945 83.666,37.861 83.666,37.608 83.443,37.385 83.443,36.898 83.783,36.558 v1(83.783,34.687)
  other v3: 76.75,36.8
DDR_RASN: R276.1 U14.J18 U17.L8 | length 26
  Top Layer w0.09: U14.J18@74.475,34.65 74.496,34.65 74.746,34.4 75.079,34.4 75.107,34.428 75.465,34.428 76.878,33.015 77.535,33.015 v3(78.475,32.075) ; U17.L8@88.25,33.45 v1(88.65,33.85)
  Signal Layer 2 w0.09: v3(78.475,32.075) 78.491,32.075 80.85,29.716 80.85,29.538 81.723,28.665 83.987,28.665 84.799,29.476 84.799,31.164 87.085,33.45 88.25,33.45 v1(88.65,33.85)
  Bottom Layer w0.09: v1(88.65,33.85) 89.205,34.405 89.205,34.414 89.436,34.645 89.774,34.645 90.16,35.032 90.16,36.585 91.24,37.665 91.275,37.665 91.55,37.94 R276.1@91.55,37.975
  other v2: 78.475,32.075
DDR_RESETN: R176.2 U14.E17 U17.P1 | length 23.5
  Top Layer w0.075: U14.E17@73.975,36.65 74.232,36.907 74.58,36.907 74.731,36.756 74.731,36.551 74.875,36.407 75.682,36.407 v3(75.95,36.675)
  Top Layer w0.09: v1(81.24,38.375) 81.276,38.339 81.276,36.897 81.045,36.666 81.045,34.476 80.86,34.291 80.86,33.527 80.09,32.757 80.09,31.153 80.192,31.051 U17.P1@82.649,31.051
  Signal Layer 2 w0.09: v3(75.95,36.675) 75.95,38.78 77.745,40.575 80.04,40.575 81.134,39.481 81.134,38.633 81.162,38.605 81.162,38.438 v1@81.25,38.35
  Bottom Layer w0.1: R176.2@80.425,38.875 80.605,38.695 80.769,38.695 81.012,38.452 81.163,38.452 v1(81.24,38.375)
  other v2: 75.95,36.675
DDR_WEN: R257.1 U14.E18 U17.L2 | length 24.2
  Top Layer w0.09: v1@83.05,33.846 U17.L2@83.453,33.443
  Signal Layer 2 w0.09: v3(74.475,36.65) 74.85,36.65 75.1,36.4 75.439,36.4 75.615,36.576 75.615,38.855 77.625,40.865 80.16,40.865 81.424,39.601 81.424,39.144 81.92,38.648 82.261,38.648 83.402,37.507 83.402,36.867 83.925,36.344 83.925,35.56 84.178,35.307 84.178,34.523 83.9,34.245 83.67,34.245 83.345,33.92 83.12,33.92 v1(83.05,33.85)
  Bottom Layer w0.09: v1@83.071,33.852 83.468,34.25 84.016,34.25 84.236,34.469 84.236,34.477 84.245,34.486 84.245,37.022 84.7,37.477 R257.1@84.7,37.945
  other v2: 74.475,36.65
DDR_ZQ: R112.2 U14.G16 | length 3
  Top Layer w0.075: U14.G16@73.475,35.65 73.725,35.4 75.17,35.4 75.295,35.275 R112.2@76.35,35.275
DSI_CKN: U14.A4 | length 0.7
  Signal Layer 2 w0.075: v3(67.475,38.65) 67.475,39.35
  other v2: 67.475,38.65
DSI_CKP: U14.B4 | length 1.3
  Signal Layer 2 w0.075: v3(67.475,38.15) 67.725,38.4 67.725,39.3
  other v2: 67.475,38.15
DSI_D0N: U14.A5 | length 0.6
  Signal Layer 2 w0.075: v3(67.975,38.65) 67.975,39.25
  other v2: 67.975,38.65
DSI_D0P: U14.B5 | length 1.2
  Signal Layer 2 w0.075: v3(67.975,38.15) 68.225,38.4 68.225,39.225
  other v2: 67.975,38.15
DSI_D1N: U14.A6 | length 0.7
  Signal Layer 2 w0.075: v3(68.475,38.649) 68.48,38.654 68.48,39.32
  other v2: 68.475,38.649
DSI_D1P: U14.B6 | length 1.2
  Signal Layer 2 w0.075: v3(68.475,38.15) 68.75,38.425 68.75,39.25
  other v2: 68.475,38.15
DSI_D2N: U14.B3 | length 1.3
  Signal Layer 2 w0.075: 66.818,39.325 66.818,38.908 66.726,38.816 66.726,38.399 v3(66.975,38.15)
  other v2: 66.975,38.15
DSI_D2P: U14.A3 | length 0.7
  Signal Layer 2 w0.075: v3(66.975,38.65) 66.975,39.325
  other v2: 66.975,38.65
DSI_D3N: U14.B2 | length 1.3
  Signal Layer 2 w0.075: 66.318,39.325 66.318,38.968 66.226,38.876 66.226,38.399 v3(66.475,38.15)
  other v2: 66.475,38.15
DSI_D3P: U14.A2 | length 0.7
  Signal Layer 2 w0.075: v3(66.475,38.65) 66.475,39.35
  other v2: 66.475,38.65
DSI_REXT: U14.C4 | length 1.8
  Signal Layer 2 w0.075: 67.225,39.348 67.225,38.047 67.44,37.833 67.44,37.685 v3(67.475,37.65)
  other v2: 67.475,37.65
eMMC.SDMMC2_CK: R103.1 U14.G14 U37.M6 | length 22.3
  Signal Layer 2 w0.075: v1@84.275,49.462 v1(84.275,49.5) ; v3@84.75,48.975 v3@84.75,48.987
  Signal Layer 2 w0.12: v2(72.475,35.65) 72.481,35.65 72.615,35.784 73.667,35.784 73.875,35.992 73.875,37.237 74.625,37.987 74.625,38.975 83,47.35 84.229,47.35 85.07,48.191 85.07,48.63 v2(84.75,48.95) v3@84.75,48.975 ; v1@84.275,49.462 v3@84.75,48.987
  Bottom Layer w0.1: v1@84.25,49.55 84.275,49.525 v1(84.275,49.5) 84.275,49.077 84.707,48.644 84.707,48.549 84.912,48.344 R103.1@85.007,48.344
  other v3: 72.475,35.65 84.75,48.95
eMMC.SDMMC2_CMD: R104.1 U14.D14 U37.M5 | length 22.8
  Signal Layer 2 w0.075: 72.394,39.674 72.394,37.922 72.226,37.753 72.226,37.399 v2(72.475,37.15)
  Signal Layer 2 w0.12: 72.395,39.675 72.395,42.473 73.715,43.792 73.715,44.172 78.792,49.25 81.525,49.25 81.6,49.325 83.475,49.325 83.925,48.875 84.325,48.875 v2(84.75,48.45) v1(84.276,47.977)
  Bottom Layer w0.11: v1@84.286,47.968 84.561,47.694 84.856,47.694 R104.1@85.011,47.538
  other v3: 72.475,37.15 84.75,48.45
eMMC.SDMMC2_D0: R101.1 U14.A16 U37.A3 | length 18.9
  Top Layer w0.11: U14.A16@73.5,38.675 73.5,41.309 76.112,43.92 76.305,43.92 76.4,43.825 76.4,43.674 74.527,41.801 74.527,41.664 74.626,41.565 74.797,41.565 76.866,43.633 76.866,43.959 76.637,44.188 76.637,44.446 v1(78.711,46.519) 78.711,47.201 78.956,47.447 U37.A3@79.251,47.447
  Bottom Layer w0.11: v1@78.721,46.511 78.721,46.624 78.892,46.795 78.892,46.839 78.916,46.863 78.916,46.958 79.116,47.158 R101.1@79.211,47.158
eMMC.SDMMC2_D1: U14.B16 U37.A4 | length 17.5
  Signal Layer 2 w0.12: v2(73.475,38.15) 73.665,38.34 73.665,39.438 74.235,40.008 74.235,40.807 73.675,41.367 73.675,41.942 73.938,42.205 74.412,42.205 74.993,41.624 75.251,41.624 75.669,42.043 75.669,42.244 74.995,42.919 74.995,43.547 75.654,44.207 76.141,44.207 76.935,43.413 77.187,43.413 79.068,45.294 79.068,45.582 78.182,46.468 78.182,46.66 79.236,47.714 79.236,47.886 v3@79.25,47.9
  other v2: 79.25,47.95
  other v3: 73.475,38.15 79.25,47.95
eMMC.SDMMC2_D2: U14.B15 U37.A5 | length 17.5
  Top Layer w0.09: U37.A5@79.225,48.45 U37.A5@79.25,48.475
  Top Layer w0.11: v2(78.9,48.45) U37.A5@79.225,48.45
  Signal Layer 2 w0.12: v2(72.975,38.15) 72.975,38.509 73.05,38.584 73.05,39.735 73.595,40.28 73.595,40.542 73.035,41.102 73.035,42.207 73.673,42.845 74.15,42.845 74.355,43.05 74.355,43.812 75.778,45.236 76.017,45.236 76.952,44.301 77.17,44.301 78.203,45.334 78.203,45.542 77.96,45.784 77.237,45.784 76.964,46.057 76.964,46.514 77.275,46.825 77.45,46.825 ; 77.446,46.829 78.596,47.979 78.596,48.196 v3@78.85,48.45
  other v3: 72.975,38.15 78.9,48.45
eMMC.SDMMC2_D3: U14.C16 U37.B2 | length 17.6
  Signal Layer 2 w0.12: v3(73.475,37.65) v3@73.568,37.65 ; v3@73.568,37.602 73.787,37.602 74.3,38.115 74.3,39.168 74.875,39.743 74.875,40.701 75.041,40.867 75.398,40.867 76.585,42.053 76.585,42.332 75.739,43.178 75.739,43.377 75.835,43.473 75.97,43.473 76.874,42.569 77.248,42.569 80.026,45.347 80.026,46.355 80.365,46.694 80.772,46.694 80.882,46.805 80.882,47.242 80.599,47.524 80.325,47.524 v3@79.751,46.95
  other v2: 73.475,37.65 79.75,46.95
  other v3: 79.75,46.95
eMMC.SDMMC2_D4: U14.D15 U37.B3 | length 18.6
  Signal Layer 2 w0.075: v2(72.975,37.15) 73.224,37.399 73.224,37.752 73.372,37.9 73.625,37.9 73.975,38.25
  Signal Layer 2 w0.12: 73.985,38.252 73.985,39.306 74.555,39.876 74.555,40.94 73.995,41.5 73.995,41.772 74.109,41.885 74.279,41.885 74.978,41.187 75.266,41.187 76.094,42.015 76.094,42.273 75.315,43.052 75.315,43.415 75.787,43.887 76.008,43.887 76.957,42.939 77.165,42.939 79.43,45.203 79.43,46.015 79.121,46.324 79.121,47.146 79.425,47.45 v2(79.75,47.45)
  other v3: 72.975,37.15 79.75,47.45
eMMC.SDMMC2_D5: U14.F15 U37.B4 | length 17.1
  Signal Layer 2 w0.12: v4(75.25,40.5) 75.632,40.5 80.346,45.214 80.346,46.223 80.497,46.374 80.904,46.374 81.202,46.672 81.202,47.374 80.652,47.924 79.776,47.924 v2(79.75,47.95)
  Signal Layer 3 w0.12: v2(72.975,36.15) 72.955,36.15 72.609,36.496 72.609,36.901 72.99,37.282 72.99,38.24 v4(75.25,40.5)
  other v3: 79.75,47.95
  other v4: 72.975,36.15
eMMC.SDMMC2_D6: U14.F14 U37.B5 | length 19.1
  Top Layer w0.11: v3(79.5,48.7) U37.B5@79.75,48.45
  Signal Layer 2 w0.075: v2(72.475,36.15) 72.615,36.29 72.615,36.865 72.725,36.975 72.725,38.675 72.79,38.752
  Signal Layer 2 w0.12: 72.79,38.752 72.79,39.978 73.149,40.336 73.149,40.536 72.715,40.969 72.715,42.34 74.035,43.66 74.035,43.945 75.646,45.556 76.149,45.556 76.866,44.839 77.113,44.839 77.281,45.007 77.281,45.269 76.642,45.907 76.642,46.645 78.737,48.74 79.02,48.74 79.06,48.7 v3(79.5,48.7)
  other v2: 79.5,48.7
  other v3: 72.475,36.15
eMMC.SDMMC2_D7: U14.C15 U37.B6 | length 18.1
  Top Layer w0.11: U37.B6@79.75,48.95 v3(80,48.7)
  Signal Layer 2 w0.075: v3@73.01,37.685 73.01,37.833 73.225,38.048 73.225,38.302 73.311,38.388 ; 78.925,47.85 78.925,47.855
  Signal Layer 2 w0.12: v2(72.975,37.65) v3@73.01,37.685 ; 73.311,38.388 73.311,39.537 73.915,40.141 73.915,40.675 73.355,41.235 73.355,42.075 73.805,42.525 74.575,42.525 74.675,42.625 74.675,42.786 74.675,43.68 75.522,44.527 76.273,44.527 76.911,43.889 77.211,43.889 78.545,45.223 78.545,45.653 77.862,46.335 77.862,46.792 78.925,47.855 78.925,48.05 79.1,48.225 79.115,48.225 79.13,48.24 79.89,48.24 80,48.35 v3(80,48.7)
  other v2: 80,48.7
  other v3: 72.975,37.65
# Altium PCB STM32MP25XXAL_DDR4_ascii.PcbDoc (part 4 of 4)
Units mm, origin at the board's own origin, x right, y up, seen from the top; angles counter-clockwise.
Board outline 125 x 95 mm, 6 copper layers (Top Layer, Signal Layer 1, Signal Layer 2, Signal Layer 3, Signal Layer 4, Bottom Layer), stack 1.403 mm thick; 220 components, 316 nets, 1103 pads, 939 vias.
Unrouted connection lines stored in the file: 5.

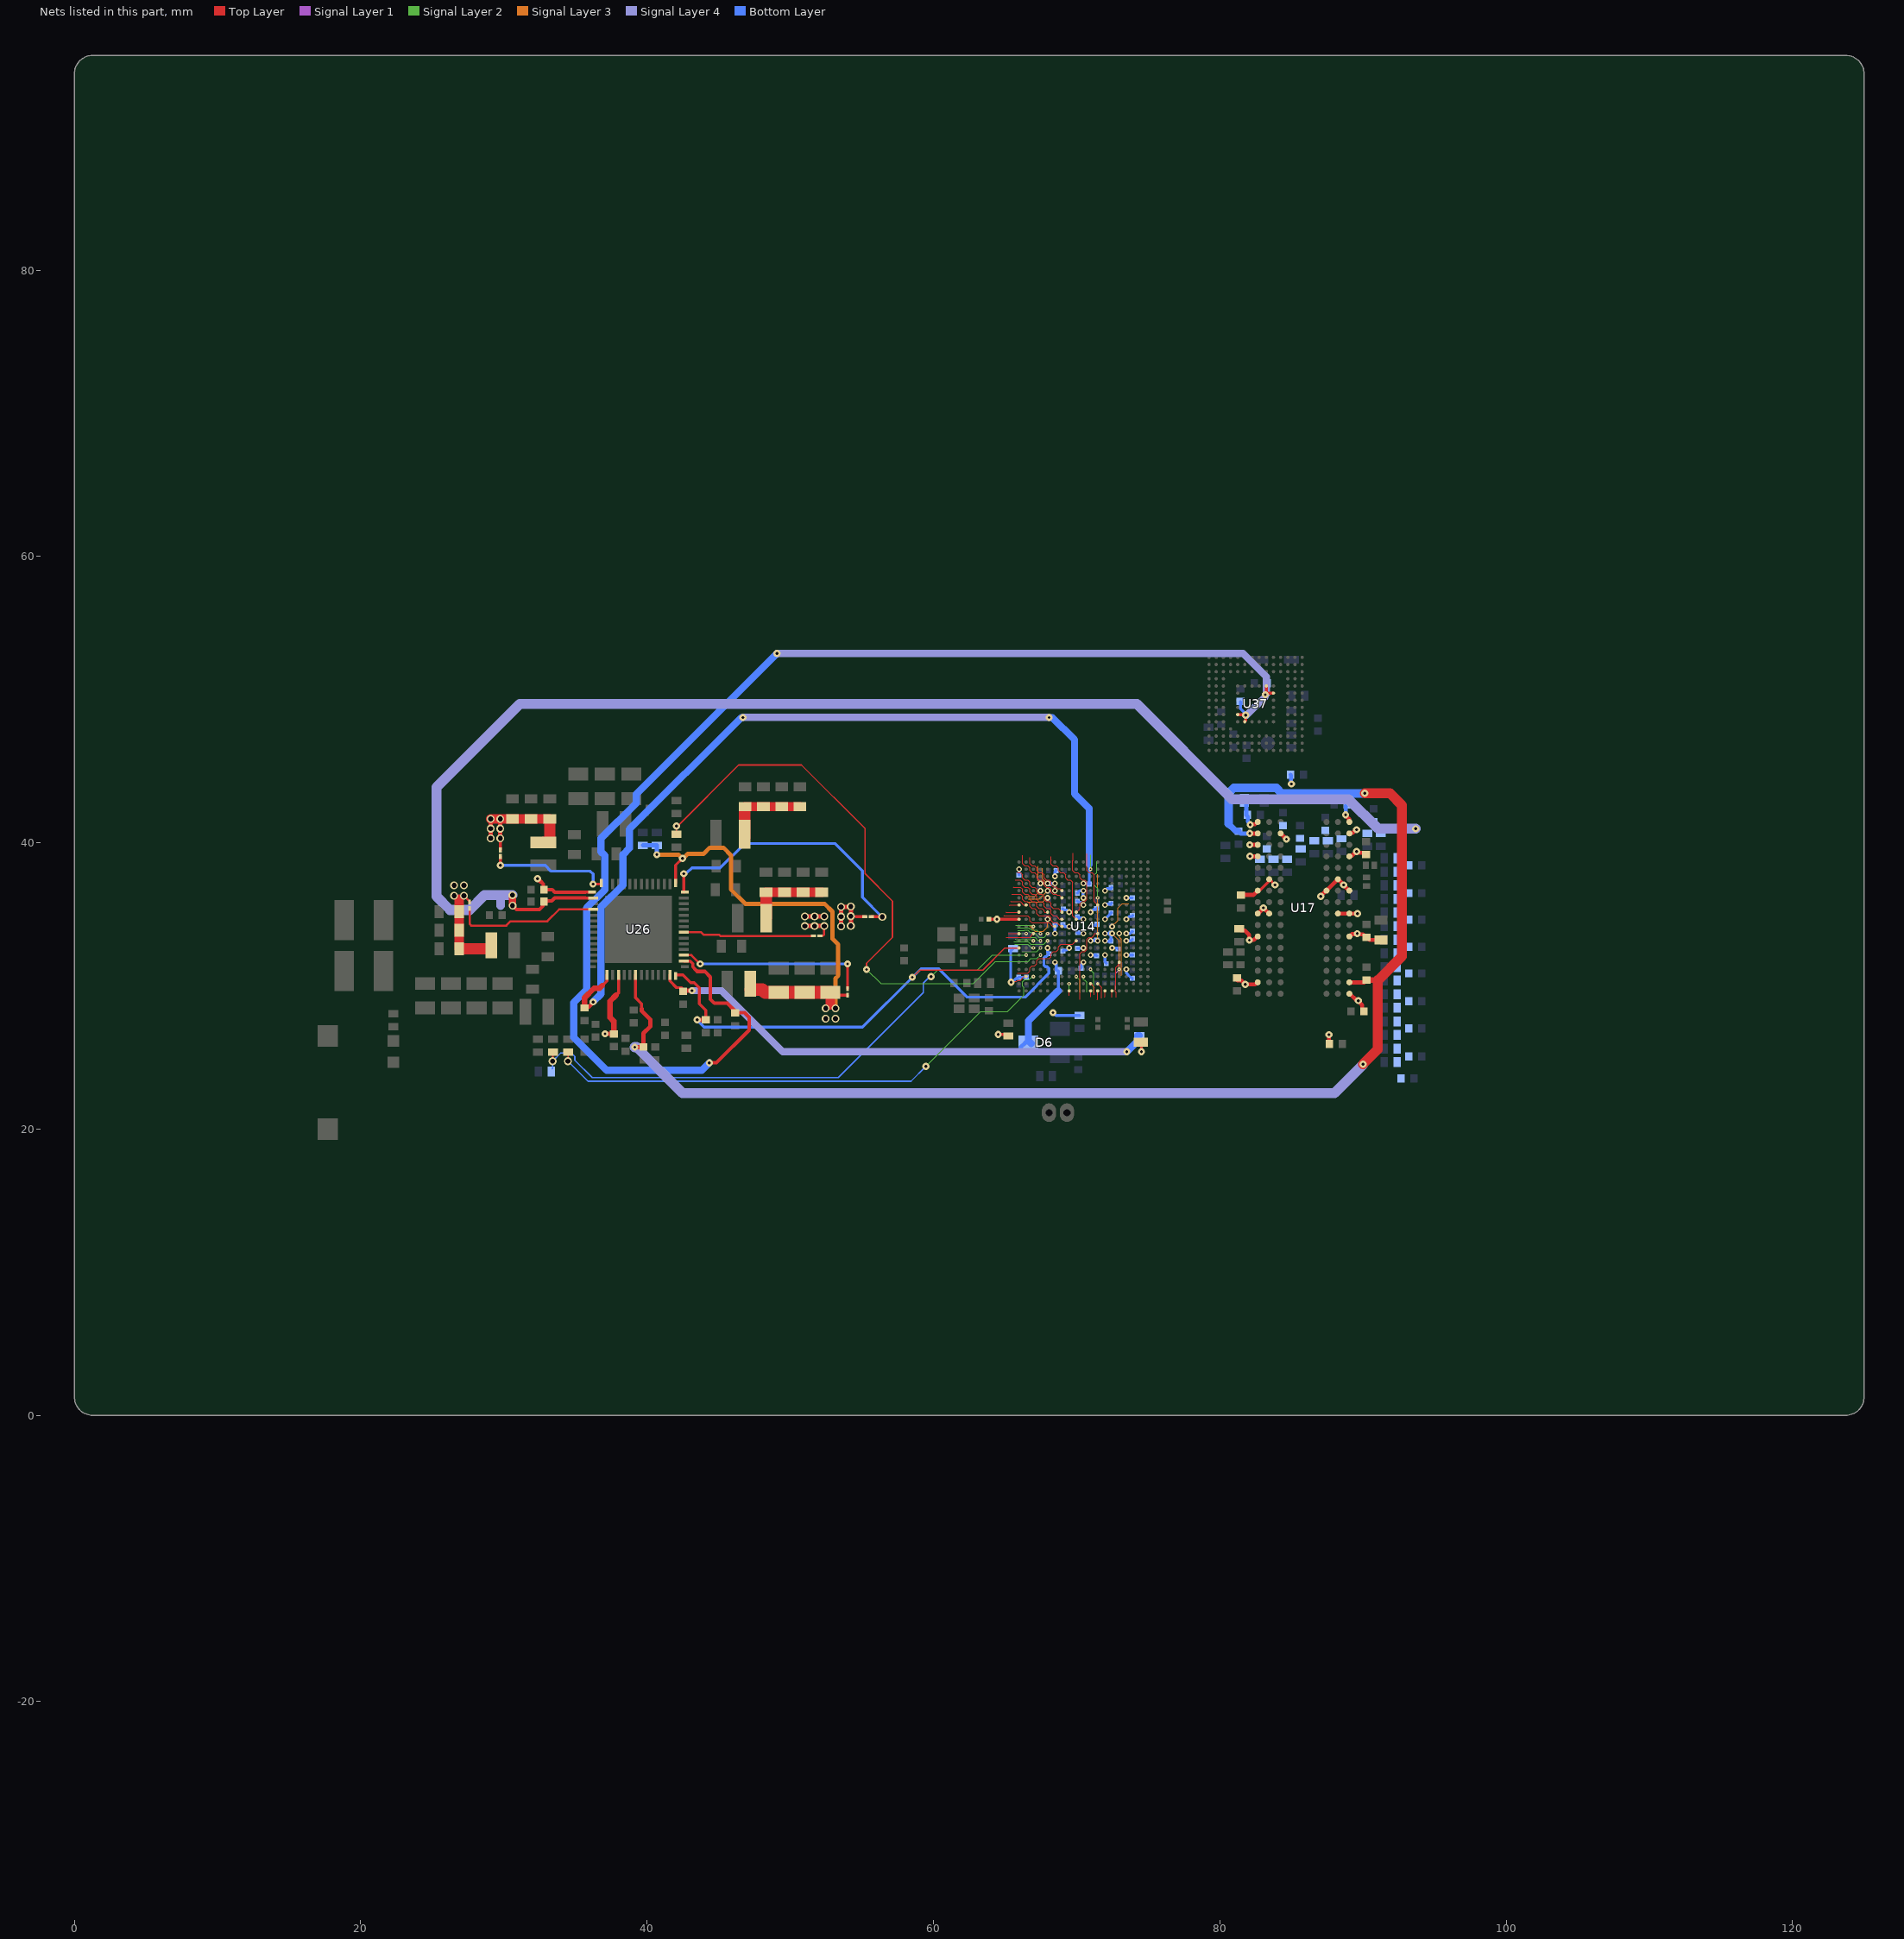
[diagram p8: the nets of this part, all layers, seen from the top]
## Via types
v1: diameter 0.5, hole 0.2, Top Layer to Bottom Layer, 292 vias
v2: diameter 0.26, hole 0.1, Top Layer to Signal Layer 1, 266 vias
v3: diameter 0.26, hole 0.1, Signal Layer 1 to Signal Layer 2, 143 vias
v4: diameter 0.4, hole 0.2, Signal Layer 1 to Signal Layer 4, 101 vias
v5: diameter 0.26, hole 0.1, Signal Layer 4 to Bottom Layer, 81 vias
v6: diameter 0.55, hole 0.35, Top Layer to Bottom Layer, 55 vias
v7: diameter 0.5, hole 0.2, Signal Layer 1 to Signal Layer 4, 1 vias

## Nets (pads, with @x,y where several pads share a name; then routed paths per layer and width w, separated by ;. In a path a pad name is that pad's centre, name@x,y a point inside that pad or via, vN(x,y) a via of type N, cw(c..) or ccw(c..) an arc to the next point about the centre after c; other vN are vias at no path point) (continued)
PG7: U14.E7 | length 3.8
  Top Layer w0.075: 66.725,38.962 66.725,38.547 66.872,38.4 66.874,38.4 66.875,38.399 67.078,38.399 67.224,38.253 67.224,38.048 67.372,37.901 67.577,37.901 67.725,37.752 67.725,37.547 67.872,37.4 68.078,37.4 68.225,37.253 68.225,37.047 68.372,36.901 68.577,36.901 68.678,36.8 68.825,36.8 U14.E7@68.975,36.65 U14.E7@69,36.65
PG8: U14.E5 | length 1.6
  Signal Layer 3 w0.075: 66.614,36.083 67.408,36.083 v4(67.975,36.65)
  other v2: 67.975,36.65
PG9: U14.G2 | length 1.2
  Top Layer w0.075: 65.375,35.925 65.407,35.893 66.075,35.893 66.218,35.75 66.218,35.707 66.25,35.675 66.275,35.65 U14.G2@66.475,35.65
PG10: U14.F5 | length 1.5
  Signal Layer 3 w0.075: 66.565,35.868 67.647,35.868 67.928,36.15 v4(67.975,36.15)
  other v2: 67.975,36.15
PG11: U14.F7 | length 4.8
  Top Layer w0.075: 66.226,39.117 66.226,38.753 66.226,38.547 66.372,38.4 66.55,38.4 66.551,38.399 66.578,38.399 66.724,38.253 66.724,38.226 ; U14.F7@68.975,36.15 68.787,36.337 68.64,36.337 68.577,36.401 68.372,36.401 68.225,36.547 68.225,36.753 68.078,36.9 67.872,36.9 67.725,37.047 67.725,37.252 67.577,37.401 67.372,37.401 67.225,37.547 67.225,37.753 67.077,37.901 66.872,37.901 66.726,38.047 66.726,38.225 ; 66.724,38.226 66.726,38.225
PG12: U14.H7 | length 4.9
  Top Layer w0.075: 65.85,37.9 66.076,37.9 66.224,37.752 66.224,37.548 66.372,37.4 66.578,37.4 66.725,37.253 66.725,37.047 66.872,36.9 67.078,36.9 67.225,36.753 67.225,36.547 67.372,36.401 67.577,36.401 67.725,36.252 67.725,36.047 67.872,35.9 68.078,35.9 68.225,35.753 68.225,35.547 68.372,35.401 68.724,35.401 U14.H7@68.975,35.15
PG13: U14.J7 | length 5
  Top Layer w0.075: 65.7,37.4 65.871,37.4 65.872,37.399 66.078,37.399 66.225,37.252 66.225,37.047 66.373,36.9 66.578,36.9 66.725,36.753 66.725,36.547 66.872,36.4 67.078,36.4 67.225,36.252 67.225,36.047 67.372,35.9 67.578,35.9 67.726,35.752 67.726,35.547 67.872,35.4 68.078,35.4 68.225,35.253 68.225,35.047 68.372,34.901 68.577,34.901 68.724,34.753 68.724,34.701 68.775,34.65 U14.J7@68.975,34.65
PG14: U14.H5 | length 3.6
  Top Layer w0.075: 65.55,36.925 65.576,36.899 66.078,36.899 66.225,36.753 66.225,36.547 66.372,36.4 66.578,36.4 66.725,36.253 66.725,36.047 66.872,35.9 67.078,35.9 67.225,35.753 67.225,35.546 67.372,35.4 67.578,35.4 67.725,35.253 67.725,35.194 67.768,35.15 U14.H5@67.975,35.15
PG15: U14.E4 | length 1.2
  Signal Layer 3 w0.075: 66.475,36.25 67.075,36.25 v4(67.475,36.65)
  other v2: 67.475,36.65
PH2: U14.L14 | length 3.1
  Signal Layer 3 w0.075: v4(72.475,33.65) 72.975,33.15 72.975,30.78
  other v2: 72.475,33.65
PH3: U14.K14 | length 2.3
  Signal Layer 3 w0.075: v4(72.475,34.15) 72.475,34.159 72.875,34.559 72.875,35.425 73.2,35.75 73.625,35.75
  other v2: 72.475,34.15
PH4: U14.G12 | length 4
  Top Layer w0.075: 70.725,39.225 70.725,38.047 70.873,37.9 71.078,37.9 71.226,37.752 71.226,35.899 U14.G12@71.475,35.65
PH5: U14.M9 | length 5.5
  Top Layer w0.075: 65.875,30.9 66.578,30.9 66.725,31.047 66.725,31.253 66.872,31.4 67.077,31.4 67.224,31.547 67.224,31.65 ; 67.226,31.65 67.226,31.753 67.372,31.899 68.077,31.899 68.224,32.047 68.224,32.252 68.372,32.399 68.577,32.399 68.724,32.547 68.724,32.699 68.747,32.722 68.747,32.753 68.894,32.901 69.725,32.901 U14.M9@69.975,33.15
PH6: U14.L15 | length 3
  Signal Layer 3 w0.075: v4(72.975,33.65) 73.008,33.617 73.008,33.392 73.136,33.264 ; 73.137,30.714 73.137,33.264
  other v2: 72.975,33.65
PH7: U14.L12 | length 5.5
  Top Layer w0.075: 70.225,29.05 70.241,29.066 70.241,29.541 70.226,29.557 70.226,30.475 70.226,31.363 70.225,31.364 70.225,32.252 70.371,32.399 70.577,32.399 70.724,32.546 70.724,32.752 70.725,32.753 70.725,33.252 70.873,33.399 71.077,33.399 71.224,33.547 71.224,33.606 71.268,33.65 U14.L12@71.475,33.65
PH8: U14.M12 | length 4.6
  Signal Layer 3 w0.075: v4(71.475,33.15) 71.475,37.775
  other v2: 71.475,33.15
PH9: U14.W8 | length 0.3
  Top Layer w0.075: 69.475,29.325 U14.W8@69.475,29.65
PH10: U14.U10 | length 1.2
  Signal Layer 2 w0.075: v2(70.475,30.65) 70.475,30.443 70.519,30.399 70.578,30.399 70.724,30.253 70.724,29.566
  other v3: 70.475,30.65
PH11: U14.T11 | length 1.7
  Signal Layer 2 w0.075: v3(70.975,31.15) 70.975,31.1 71.2,30.875 71.2,29.518
  other v2: 70.975,31.15
PH12: U14.V8 | length 0.6
  Signal Layer 2 w0.075: 69.475,29.6 v3(69.475,30.15)
  other v2: 69.475,30.15
PH13: U14.U9 | length 1.2
  Signal Layer 2 w0.075: v3(69.975,30.65) 70.225,30.4 70.225,29.572
  other v2: 69.975,30.65
PI0: U14.H1 | length 0.9
  Top Layer w0.075: 65.05,35.175 65.075,35.15 U14.H1@65.975,35.15
PI1: U14.J9 | length 5.5
  Top Layer w0.075: 68.2,39.035 68.2,38.778 68.224,38.753 68.224,38.501 68.326,38.399 68.578,38.399 68.728,38.25 68.728,38.054 68.877,37.905 69.073,37.905 69.225,37.752 69.225,37.547 69.373,37.4 69.578,37.4 69.726,37.252 69.726,34.899 U14.J9@69.975,34.65
PI2: U14.J5 | length 2.6
  Signal Layer 3 w0.075: 66.175,34.225 66.675,34.225 67.091,33.809 67.663,33.809 67.975,34.121 v4(67.975,34.65)
  other v2: 67.975,34.65
PI3: U14.H9 | length 5.2
  Top Layer w0.075: 69.75,39.258 69.75,38.768 69.726,38.743 69.726,38.047 69.873,37.9 70.078,37.9 70.225,37.753 70.225,37.547 70.372,37.4 70.578,37.4 70.725,37.252 70.725,36.048 70.577,35.899 70.372,35.899 70.217,35.745 70.217,35.393 U14.H9@69.975,35.15
PI4: U14.G1 | length 0.7
  Top Layer w0.075: 65.325,35.625 65.35,35.65 U14.G1@65.975,35.65
PI5: U14.K7 | length 4.9
  Top Layer w0.075: 65.476,36.399 66.078,36.399 66.226,36.252 66.226,36.047 66.381,35.891 66.566,35.891 66.722,35.734 66.722,35.55 66.872,35.4 67.078,35.4 67.225,35.253 67.225,35.047 67.372,34.901 68.077,34.901 68.224,34.753 68.224,34.55 68.249,34.526 68.249,34.524 68.372,34.401 68.649,34.401 68.87,34.18 68.945,34.18 U14.K7@68.975,34.15
PI6: U14.D4 | length 1.3
  Signal Layer 3 w0.075: 67.323,38.375 67.323,37.356 67.475,37.204 v4(67.475,37.15)
  other v2: 67.475,37.15
PI7: U14.D5 | length 1.2
  Signal Layer 3 w0.075: 67.625,38.225 67.625,37.5 v4@67.975,37.15
  other v2: 67.975,37.15
  other v4: 67.975,37.15
PI8: U14.N4 | length 1.4
  Signal Layer 2 w0.075: 66.2,32.4 67.225,32.4 v3(67.475,32.65)
  other v2: 67.475,32.65
PI9: U14.K6 | length 4
  Top Layer w0.075: 64.9,34.925 64.926,34.899 66.578,34.899 66.724,34.753 66.724,34.575 66.726,34.574 66.726,34.547 66.872,34.401 68.078,34.401 68.316,34.162 68.463,34.162 U14.K6@68.475,34.15
PI10: U14.B11 | length 1
  Signal Layer 2 w0.075: v3(70.975,38.15) 70.975,39.15
  other v2: 70.975,38.15
PI11: U14.F12 | length 2.7
  Signal Layer 2 w0.075: 71.395,38.656 71.395,37.923 71.226,37.753 71.226,37.047 71.475,36.797 v3(71.475,36.15)
  other v2: 71.475,36.15
PMIC_WAKEUPn: R46.1 U14.P4 | length 42.1
  Top Layer w0.1: R46.1@42.048,40.587 42.048,41.081 46.399,45.432 50.777,45.432 55.214,40.995 55.214,37.847 57.138,35.924 57.138,33.388 55.328,31.578 v1(55.328,31.139)
  Signal Layer 2 w0.075: v1@55.325,31.15 56.325,30.15 62.775,30.15 64.34,31.715 66.616,31.715 66.801,31.899 67.225,31.899 v3(67.475,32.15)
  other v1: 42.048,41.172
  other v2: 67.475,32.15
PWR_CPU_ON: R60.1 R272.2 U14.P2 | length 39.3
  Top Layer w0.1: v6(33.398,24.739) 33.412,24.753 33.412,25.368 R60.1@33.428,25.384
  Signal Layer 2 w0.075: v1(59.825,30.65) 60.275,31.1 63.05,31.1 64.1,32.15 v2(66.475,32.15)
  Bottom Layer w0.1: R272.2@33.37,24.205 33.399,24.234 v6@33.399,24.737 ; v6(33.398,24.739) 33.959,25.3 34.725,25.3 34.95,25.075 34.95,24.8 36.166,23.584 53.344,23.584 59.297,29.537 59.297,30.197 v1@59.8,30.7
  other v3: 66.475,32.15
PWR_ON: R2.1 U14.U3 | length 37.4
  Top Layer w0.1: v6(34.473,24.739) 34.478,24.744 R2.1@34.478,25.384
  Signal Layer 2 w0.075: v1(59.475,24.375) 63.3,28.2 65.175,28.2 66.325,29.35 66.325,29.87 66.226,29.97 66.226,30.282 66.369,30.425 66.664,30.425 66.804,30.566 66.84,30.566 66.925,30.65 v3(66.975,30.65)
  Bottom Layer w0.1: v6(34.473,24.739) 35.878,23.334 58.434,23.334 v1(59.475,24.375)
  other v2: 66.975,30.65
PZ0: U14.L5 | length 2.4
  Signal Layer 2 w0.075: 65.894,33.875 66.347,33.875 66.372,33.899 66.578,33.899 66.742,33.736 66.839,33.736 66.875,33.7 67.072,33.7 67.372,33.4 67.726,33.4 v3(67.975,33.65)
  other v2: 67.975,33.65
PZ1: U14.M4 | length 1.8
  Signal Layer 2 w0.075: 65.825,33.4 67.078,33.4 67.087,33.391 67.292,33.185 67.44,33.185 v3(67.475,33.15)
  other v2: 67.475,33.15
PZ2: U14.M3 | length 1.3
  Signal Layer 2 w0.075: 65.71,33.281 65.722,33.281 65.76,33.243 66.794,33.243 66.852,33.185 66.94,33.185 v3(66.975,33.15)
  other v2: 66.975,33.15
PZ3: U14.M5 | length 2.5
  Signal Layer 2 w0.075: 65.625,33.075 66.625,33.075 66.799,32.901 67.703,32.901 67.953,33.15 v3(67.975,33.15)
  other v2: 67.975,33.15
PZ4: U14.L4 | length 1.8
  Signal Layer 2 w0.075: 65.868,34.04 66.279,34.04 66.303,34.064 66.647,34.064 66.711,34 66.772,34 66.872,33.901 67.224,33.901 v3(67.475,33.65)
  other v2: 67.475,33.65
PZ5: U14.N3 | length 1.4
  Signal Layer 2 w0.075: 65.678,32.9 66.578,32.9 66.724,32.753 66.724,32.749 66.803,32.671 66.954,32.671 v3(66.975,32.65)
  other v2: 66.975,32.65
PZ6: U14.K3 | length 1.3
  Signal Layer 2 w0.075: 65.755,34.225 66.23,34.225 66.235,34.229 66.715,34.229 66.72,34.225 66.85,34.225 66.925,34.15 v3(66.975,34.15)
  other v2: 66.975,34.15
PZ7: U14.L1 | length 0.8
  Top Layer w0.075: 65.225,33.65 U14.L1@65.975,33.65
PZ8: U14.L3 | length 2
  Top Layer w0.075: 65.083,33.4 66.725,33.4 U14.L3@66.975,33.65
PZ9: U14.L2 | length 0.5
  Signal Layer 2 w0.075: 65.95,33.65 v3(66.475,33.65)
  other v2: 66.475,33.65
UCPD1_CC1: U14.W13 | length 0.4
  Top Layer w0.075: 71.95,29.225 71.975,29.25 U14.W13@71.975,29.65
UCPD1_CC2: U14.W14 | length 0.5
  Top Layer w0.075: 72.475,29.2 U14.W14@72.475,29.65
USB3DR_DM: U14.V12 | length 1.1
  Top Layer w0.075: U14.V12@71.475,30.15 71.725,29.9 71.725,29.125
USB3DR_DP: U14.W12 | length 0.6
  Top Layer w0.075: 71.45,29.05 71.475,29.075 U14.W12@71.475,29.65
USB3DR_TXRTUNE: U14.R15 | length 2.6
  Top Layer w0.075: 72.775,29.203 72.775,29.518 72.71,29.584 72.71,30.032 72.725,30.047 72.725,31.274 72.952,31.502 72.952,31.627 U14.R15@72.975,31.65
USBH_HS_DM: U14.V11 | length 0.9
  Top Layer w0.075: U14.V11@70.975,30.15 71.225,29.9 71.225,29.375
USBH_HS_DP: U14.W11 | length 0.4
  Top Layer w0.075: 70.975,29.225 U14.W11@70.975,29.65
USBH_HS_TXRTUNE: U14.T15 | length 1.5
  Signal Layer 1 w0.075: 72.725,29.75 72.725,30.9 v2(72.975,31.15)
VBAT: C87.2 D6.3 U14.R6 | length 7.3
  Bottom Layer w0.2: v5(68.475,31.65) 68.475,31.634 68.575,31.534 C87.2@68.575,31.1 ; 68.725,29.654 C87.2@68.725,31.05
  Bottom Layer w0.3: D6.3@66.076,25.692 66.426,26.042 D6.3@66.626,26.042
  Bottom Layer w0.5: D6.3@66.825,25.975 66.626,26.174 66.626,27.555 68.725,29.654
  other v2: 68.475,31.65
  other v4: 68.475,31.65
VDD3V3_USB: C156.2 R286.1 U26.13 | length 36
  Top Layer w0.21: U26.13@41.598,30.769 41.598,30.339 42.061,29.876 42.316,29.876 42.318,29.874 42.388,29.874 42.523,29.739 C156.2@42.523,29.669
  Top Layer w0.3: C156.2@42.523,29.669 v1(43.133,29.669)
  Signal Layer 4 w0.5: v1@43.134,29.668 45.207,29.668 49.475,25.4 v1(73.5,25.4)
  Bottom Layer w0.5: v1(73.5,25.4) 74.275,26.175 74.275,26.52 74.28,26.525 R286.1@74.375,26.525
VDD_DDR: C39.2 C41.2 C70.2 C82.2 C104.2 C105.2 C106.2 C112.2 C172.2 C175.1 C178.2 C179.2 C181.2 C192.1 C200.2 C202.2 C211.1 C218.2 C284.1 C304.1 C306.1 L5.2 LNK8.2 R116.1 U14.F16 U14.J16 U14.L16 U14.M16 U14.P16 U14.T16 U17.A1 U17.A9 U17.B3 U17.B9 U17.C1 U17.D1 U17.D9 U17.F2 U17.F8 U17.G1 U17.G7 U17.G9 U17.J1 U17.J2 U17.J8 U17.J9 U17.L1 U17.L9 U17.R1 U17.T9 U26.43 | length 38.3
  Top Layer w0.15: v6(27.196,36.304) 27.598,35.902 LNK8.2@27.598,35.862
  Top Layer w0.2: U17.J1@82.65,35.05 U17.J1@82.673,35.05 ; U17.G1@82.692,36.692 82.827,36.692 83.408,37.273 83.408,37.408 U17.F2@83.45,37.45 v1(83.85,37.05) ; v1@83.05,35.427 v1(83.05,35.45)
  Top Layer w0.21: 35.673,36.539 U26.43@36.223,36.539
  Top Layer w0.25: 32.593,37.264 32.597,37.264 32.743,37.118 32.743,36.824 C39.2@32.853,36.714 ; C39.2@32.903,36.714 33.373,36.714 33.548,36.539 35.673,36.539
  Top Layer w0.28: C104.2@81.12,30.485 81.235,30.37 81.511,30.37 81.776,30.105 v1(81.785,30.105) 82.467,30.105 82.612,30.25 U17.R1@82.65,30.25 ; R116.1@81.35,33.985 81.465,33.87 81.755,33.87 82.054,33.571 82.054,33.192 v1(82.058,33.188) ; C105.2@81.46,36.355 82.355,36.355 U17.G1@82.65,36.65 ; v1@82.075,33.2 82.375,33.2 82.625,33.45 U17.L1@82.65,33.45 ; v1(82.125,41.25) 82.167,41.292 82.454,41.292 82.612,41.45 U17.A1@82.65,41.45 ; U17.G1@82.612,36.65 U17.G1@82.65,36.65 ; U17.G1@82.692,36.692 U17.G1@82.65,36.65 ; v1(83.05,35.45) U17.J2@83.45,35.05 ; v1@87.06,36.265 87.06,36.273 U17.G7@87.45,36.662 ; U17.G7@87.45,36.65 U17.F8@88.25,37.45 88.615,37.085 v1@88.625,37.085 ; C82.2@87.625,25.945 v1@87.625,26.59 ; U17.J8@88.25,35.05 U17.J9@89.05,35.05 89.057,35.043 89.607,35.043 v1(89.61,35.04) ; U17.J8@88.251,35.019 U17.J8@88.276,35.019 ; v1@88.686,37.014 U17.G9@89.05,36.65 ; v1(88.79,41.957) 88.79,41.897 89.023,41.664 89.023,41.452 U17.A9@89.05,41.425 ; U17.T9@89.05,29.45 89.085,29.45 89.527,29.008 89.638,29.008 v1(89.68,28.966) ; U17.L9@89.05,33.45 89.077,33.45 89.239,33.612 89.562,33.612 v1(89.6,33.65) ; U17.D9@89.05,39.05 89.077,39.077 89.233,39.077 89.541,39.385 89.61,39.385 89.695,39.3 90.125,39.3 C178.2@90.24,39.185 ; U17.B9@89.05,40.65 89.077,40.677 89.272,40.677 89.5,40.905 v1(89.56,40.905) ; U17.A9@89.05,41.45 U17.A9@89.05,41.454 ; v1@89.6,33.596 v1(89.6,33.65) ; v1@89.691,28.925 89.955,28.661 89.955,28.39 C106.2@90.07,28.275 ; C112.2@91.27,33.205 90.455,33.205 90.265,33.395 C181.2@90.24,33.395 90.215,33.395 90.002,33.608 89.642,33.608 v1(89.6,33.65)
  Top Layer w0.3: v1@32.342,37.515 32.593,37.264 ; v1(82.1,39.05) U17.D1@82.65,39.05 ; v1@82.1,39.85 U17.C1@82.65,39.85 ; U17.J1@82.673,35.05 v1@83.05,35.427 ; U17.B3@84.25,40.65 v1(84.65,40.25)
  Top Layer w0.64: C202.2@26.873,32.589 C41.2@26.873,33.889 C200.2@26.873,35.189 ; 26.873,35.634 26.873,36.064
  Top Layer w0.8: C202.2@27.098,32.589 L5.2@28.873,32.589
  Bottom Layer w0.2: v4(73.475,31.15) 73.475,30.875 73.75,30.6 73.825,30.6 C284.1@73.9,30.525 C284.1@73.9,30.45 ; v4(73.475,32.15) C192.1@73.925,32.15 ; v4(73.475,33.15) 73.775,33.15 C306.1@73.9,33.275 ; v4(73.475,33.65) 73.725,33.65 73.875,33.8 C211.1@73.925,33.8 ; v2(73.475,34.65) 73.675,34.85 73.85,34.85 C175.1@73.925,34.925 ; v4(73.475,36.15) C304.1@73.9,36.15
  Bottom Layer w0.28: C172.2@81.71,42.955 C172.2@81.85,42.815 ; C218.2@81.85,41.935 81.965,41.82 81.965,41.47 82.125,41.31 v1(82.125,41.25) ; C70.2@84.95,44.745 84.975,44.72 84.975,44.11 v1@85,44.085 ; v1(88.79,41.957) 88.79,42.575 C179.2@88.88,42.665
  Bottom Layer w0.3: C218.2@81.85,41.935 C172.2@81.85,42.815
  other v1: 87.62,26.595 87.05,36.25 88.65,37.05 32.348,37.487 89.55,39.385 82.09,39.85 85,44.1
  other v2: 73.475,31.15 73.475,32.15 73.475,33.15 73.475,33.65 73.475,36.15
  other v4: 73.475,34.65
  other v5: 73.475,31.15 73.475,32.15 73.475,33.15 73.475,33.65 73.475,34.65 73.475,36.15
  other v6: 26.521,36.304 26.521,37.029 27.196,37.029
VDD_DDR_FB: LNK8.1 U26.46 | length 10.2
  Top Layer w0.15: LNK8.1@27.598,35.412 27.598,34.329 27.715,34.212 30.165,34.212 30.465,34.512 31.135,34.512 31.137,34.514 33.025,34.514 33.85,35.339 U26.46@36.228,35.339
VDD_EMMC: C9.2 C117.2 C190.1 U26.16 U37.E6 U37.F5 U37.J10 U37.K9 | length 97.6
  Top Layer w0.2: U37.E6@81.25,48.95 v1@81.8,48.95 ; U37.F5@81.751,48.447 81.751,48.459 81.8,48.508 v1(81.8,48.915) ; v1(83.176,50.347) v1@83.251,50.422 ; U37.J10@83.251,50.947 83.251,50.517 83.243,50.509 83.243,50.43 v1@83.251,50.422 ; U37.K9@83.751,50.447 83.371,50.447 83.338,50.414 83.259,50.414 v1@83.251,50.422
  Top Layer w0.21: U26.16@42.568,31.739 42.998,31.739 43.186,31.551 43.186,31.326 43.332,31.18
  Top Layer w0.25: 43.33,31.177 43.496,31.011 44.026,31.011 44.423,30.614 44.423,29.064 44.698,28.789 45.593,28.789 46.148,28.234 C190.1@46.148,28.164 ; v1(44.35,24.625) 44.841,24.625 47.123,26.907 47.123,27.807 46.81,28.12 C190.1@46.164,28.12
  Signal Layer 4 w0.5: v1(49.075,53.225) 81.625,53.225 83.25,51.6 83.25,50.375 v1@83.2,50.325 ; v1(81.8,48.915) 81.888,48.915 83.176,50.203 v1(83.176,50.347)
  Bottom Layer w0.2: C9.2@81.451,49.863 81.451,49.357 v1@81.72,49.088 ; v1@83.186,50.338 83.186,51.023 C117.2@83.311,51.148
  Bottom Layer w0.5: v1(44.35,24.625) 43.825,24.1 37.182,24.1 34.875,26.407 34.875,28.825 35.775,29.725 35.775,35.445 37.054,36.724 37.054,39.096 36.775,39.375 36.775,40.309 39.252,42.786 39.252,43.402 v1(49.075,53.225)
VDD_SDCARD: C142.1 U26.4 | length 5.1
  Top Layer w0.21: 37.823,29.339 37.998,29.514 U26.4@37.998,30.769
  Top Layer w0.3: v1(37.063,26.649) C142.1@37.673,26.649
  Top Layer w0.4: C142.1@37.673,26.649 37.673,27.532 37.408,27.797 37.408,28.924 37.823,29.339
VDDA1V8_AON: C189.2 C234.2 U14.N1 U14.N5 U26.14 | length 43.6
  Top Layer w0.1: v1(58.525,30.6) 58.536,30.6 59.041,31.104 63.444,31.104 64.976,32.636 65.323,32.636 65.961,32.636 U14.N1@65.975,32.65
  Top Layer w0.21: U26.14@41.998,30.769 42.508,30.769 43.046,30.231 43.286,30.231 43.643,29.873 43.643,28.741 44.098,28.286 C189.2@44.098,27.629
  Top Layer w0.3: v1(43.488,27.629) C189.2@44.098,27.629
  Bottom Layer w0.2: v1@43.469,27.63 43.974,27.126 55.051,27.126 v1(58.525,30.6) 59.125,31.2 60.375,31.2 62.364,29.211 66.397,29.211 68.07,30.884 68.07,31.221 67.953,31.338 67.82,31.338 67.713,31.445 67.713,31.945 67.82,32.052 67.878,32.052 67.995,32.169 C234.2@68.07,32.245 ; v4(67.975,32.65) 67.975,32.35 67.995,32.33 67.995,32.32 C234.2@68.065,32.25
  other v2: 67.975,32.65
  other v5: 67.975,32.65
VDDCORE: C16.2 C22.2 C23.2 C24.2 C183.2 C195.1 C196.2 C201.2 C203.1 C213.2 C215.2 C289.2 C299.2 C300.2 L2.2 LNK2.2 R11.1 U14.B1 U14.C6 U14.G10 U14.H11 U14.J1 U14.J10 U14.K11 U14.L10 U14.N8 U14.N10 | length 17
  Top Layer w0.2: C22.2@50.673,42.514 C22.2@50.721,42.562 ; 54.598,34.839 LNK2.2@55.214,34.839 ; C201.2@63.9,34.65 v1(64.425,34.65) ; v1@64.425,34.625 64.45,34.65 U14.J1@65.975,34.65 ; R11.1@74.475,26.075 74.525,26.025 v1(74.525,25.4) v1@74.525,25.375
  Top Layer w0.3: v6(53.554,34.163) v6(53.554,34.838) v6(53.554,35.513) 54.229,35.513 v6@54.229,34.163
  Top Layer w0.64: C183.2@46.848,42.514 C24.2@48.123,42.514 C23.2@49.398,42.514 C22.2@50.673,42.514
  Top Layer w0.8: L2.2@46.813,40.339 L2.2@46.813,40.589 C183.2@46.813,42.312
  Bottom Layer w0.2: C215.2@65.975,37.75 v4(65.975,38.15) ; v4(68.475,37.65) 68.475,37.98 C16.2@68.55,38.055 ; C300.2@69.05,32.425 69.125,32.5 69.309,32.5 69.459,32.65 v2(69.475,32.65) ; C195.1@70.05,32.625 70.434,32.625 70.459,32.65 v2(70.474,32.649) ; C289.2@70.05,33.725 70.083,33.692 70.417,33.692 70.459,33.65 v2(70.475,33.65) ; C196.2@70.05,34.825 70.125,34.75 70.359,34.75 70.459,34.65 v2(70.475,34.65) ; C213.2@70.05,35.925 70.125,35.85 70.275,35.85 v2(70.475,35.65) ; v2(70.975,34.15) 70.991,34.15 71.073,34.232 71.327,34.232 C203.1@71.4,34.305 ; v2(70.975,35.15) 70.991,35.15 71.171,35.33 71.325,35.33 C299.2@71.4,35.405
  other v2: 68.475,37.65 65.975,38.15
  other v4: 69.475,32.65 70.474,32.649 70.475,33.65 70.975,34.15 70.475,34.65 70.975,35.15 70.475,35.65
  other v5: 69.475,32.65 70.474,32.649 70.475,33.65 70.975,34.15 70.475,34.65 70.975,35.15 70.475,35.65 68.475,37.65 65.975,38.15
  other v6: 54.224,34.193 54.224,34.868 54.224,35.543
VDDCORE_FB: LNK2.1 U26.28 | length 20.6
  Top Layer w0.2: U26.28@42.568,36.539 v1(42.568,37.839) ; LNK2.1@55.664,34.839 v6@56.274,34.839
  Bottom Layer w0.2: v1@42.544,37.837 42.601,37.894 42.775,37.894 43.128,38.248 45.108,38.248 46.801,39.941 53.147,39.941 55.049,38.039 55.049,36.178 v6@56.407,34.82 ; v1@42.549,37.84 42.606,37.898 42.78,37.898 43.133,38.251
  other v6: 56.431,34.822
VDDCPU: C26.2 C27.2 C28.2 C177.1 C191.1 C194.2 C283.2 C287.2 L3.2 LNK4.1 U14.E13 U14.G13 U14.J13 U14.L13 U14.M13 | length 13.3
  Top Layer w0.2: LNK4.1@29.748,39.489 v6(29.748,40.312)
  Top Layer w0.3: v6(29.073,40.312) v6(29.073,40.987) v6(29.073,41.662) v6(29.748,41.662) v6(29.748,40.987) v6(29.748,40.312)
  Top Layer w0.64: v6(29.073,41.662) 29.073,41.664 C27.2@30.598,41.664 C28.2@31.898,41.664 C26.2@33.198,41.664
  Top Layer w0.8: L3.2@32.748,40.014 33.198,40.014 33.198,41.312
  Bottom Layer w0.2: v2(71.975,33.65) C194.2@72.4,33.65 ; v2(71.975,34.65) C177.1@72.4,35.075 ; v2(71.975,35.65) 71.991,35.65 72.058,35.717 72.367,35.717 C191.1@72.45,35.8 ; v2(71.975,36.65) 72.125,36.8 72.4,36.8 C287.2@72.475,36.875 ; v5@72,33.125 C283.2@72.4,33.125 ; C283.2@72.375,33.1 C283.2@72.4,33.125 ; C194.2@72.4,33.675 C194.2@72.4,33.65 ; C177.1@72.4,35.1 C177.1@72.425,35.1 ; C194.2@72.425,33.65 C194.2@72.4,33.65 ; C283.2@72.4,33.125 C194.2@72.4,33.65
  other v2: 71.975,33.15
  other v4: 71.975,33.15 71.975,33.65 71.975,34.65 71.975,35.65 71.975,36.65
  other v5: 71.975,33.15 71.975,33.65 71.975,34.65 71.975,35.65 71.975,36.65
VDDCPU_FB: LNK4.2 U26.42 | length 8.6
  Top Layer w0.2: v1(29.748,38.429) LNK4.2@29.748,39.039 ; v1(36.223,37.114) U26.42@36.793,37.114
  Bottom Layer w0.2: v1(29.748,38.429) 32.878,38.427 33.293,38.012 36.022,38.012 36.224,37.81 v1@36.224,37.112
VDDGPU: C1.2 C2.2 C3.2 C4.2 C5.2 C34.2 C35.2 C36.2 C37.2 L4.2 LNK7.2 U14.M11 U14.N14 U14.P11 U14.P13 U14.R10 | length 11.6
  Top Layer w0.15: LNK7.2@52.073,33.489 52.08,33.497 52.283,33.497 52.371,33.584 v6(52.371,34.177)
  Top Layer w0.2: C35.2@52.448,36.531 C35.2@52.496,36.484
  Top Layer w0.3: v6(51.021,34.177) v6(51.696,34.177) v6(52.371,34.177) ; v6(51.021,34.852) v6(51.696,34.852) v6(52.371,34.852)
  Top Layer w0.64: C37.2@48.298,36.539 C36.2@49.598,36.539 C34.2@50.898,36.539 C35.2@52.198,36.539
  Top Layer w0.8: L4.2@48.323,34.739 48.323,36.212
  Bottom Layer w0.2: C2.2@70.25,31.225 70.315,31.29 70.315,31.491 v2(70.474,31.65) ; v5(70.975,32.15) 71.355,32.15 C1.2@71.4,32.105 ; v2(70.975,33.149) 70.991,33.149 71.023,33.181 71.376,33.181 C3.2@71.4,33.205 ; v2(71.975,32.15) 71.975,31.675 C4.2@72.075,31.575 ; v2(72.475,32.65) 72.825,32.65 C5.2@72.9,32.575
  other v2: 70.975,32.15
  other v4: 70.474,31.65 70.975,32.15 71.975,32.15 72.475,32.65 70.975,33.149
  other v5: 70.474,31.65 71.975,32.15 72.475,32.65 70.975,33.149
VDDGPU_FB: LNK7.1 U26.21 | length 9.3
  Top Layer w0.15: U26.21@42.448,33.739 43.781,33.739 43.958,33.562 45.038,33.562 45.111,33.489 LNK7.1@51.623,33.489
VDDIO: C17.2 C19.2 C186.2 C187.2 C197.2 C205.2 C219.2 C307.1 L6.2 LNK11.2 R27.2 R67.2 R260.2 R261.2 U14.D6 U14.E6 U14.E10 U14.F10 U14.H8 U14.K8 U14.L6 U26.29 | length 40.2
  Top Layer w0.2: U26.29@41.998,37.184 41.998,38.437 v1(42.473,38.912) ; C186.2@52.798,29.539 52.983,29.354 LNK11.2@53.998,29.354 ; v1(64.525,26.6) 64.538,26.613 65.213,26.613 R27.2@65.225,26.625
  Top Layer w0.64: 52.798,28.664 C186.2@52.798,29.094
  Top Layer w0.9: L6.2@47.248,29.739 48.048,29.739 48.248,29.539 C187.2@49.198,29.539 C19.2@50.998,29.539 C186.2@52.798,29.539
  Signal Layer 3 w0.3: v1@40.683,39.165 42.198,39.165 42.449,38.914 v1@42.474,38.914 ; v1@42.474,38.911 42.528,38.911 42.839,39.222 43.942,39.222 44.372,39.651 45.33,39.651 45.854,39.127 45.854,36.739 46.855,35.738 52.398,35.738 52.95,35.186 52.95,33.294 53.35,32.894 53.35,30.711 53.151,30.513 v6(53.15,28.424)
  Bottom Layer w0.1: v4(68.475,36.65) v4(68.475,37.15)
  Bottom Layer w0.2: C17.2@68.045,37.15 v4(68.475,37.15) ; v5(68.341,28.116) 68.383,28.116 68.558,27.941 R67.2@70.199,27.941 ; v2(68.475,33.65) 68.475,34.2 C197.2@68.55,34.275 ; C197.2@68.5,34.275 68.525,34.25 C197.2@68.575,34.2 ; C205.2@69.025,35.375 69.1,35.3 69.325,35.3 v2(69.475,35.15) ; C307.1@69.05,34.275 69.175,34.15 v2(69.475,34.15) ; C219.2@70.05,36.475 70.214,36.639 v5@70.464,36.639 ; v5(70.474,36.149) 70.463,36.16 70.463,36.203 70.45,36.215 70.45,36.583 70.464,36.596 v5@70.464,36.639 ; v4(70.475,36.65) v5@70.464,36.639
  Bottom Layer w0.3: R260.2@39.709,39.82 40.684,39.82 40.673,39.81 40.673,39.178 v1@40.663,39.168
  other v1: 40.682,39.166
  other v2: 70.474,36.149 68.475,36.65 70.475,36.65 68.475,37.15
  other v4: 68.475,33.65 69.475,34.15 69.475,35.15 70.474,36.149
  other v5: 68.475,33.65 69.475,34.15 69.475,35.15 68.475,36.65 70.475,36.65 68.475,37.15
  other v6: 52.475,27.699 53.15,27.699 52.475,28.424
  other v7: 68.35,28.125
VDDIO_FB: LNK11.1 U26.17 | length 13.4
  Top Layer w0.15: U26.17@42.568,32.139 43.098,32.139 43.701,31.536 v1(43.713,31.536)
  Top Layer w0.2: LNK11.1@53.998,29.804 v1(53.998,31.539)
  Bottom Layer w0.15: v1@53.996,31.534 v1@53.999,31.537
  Bottom Layer w0.2: v1(43.713,31.536) v1@53.996,31.534
VDDIO_SDCARD: C210.2 C217.1 U14.D10 U26.2 | length 63
  Top Layer w0.21: 36.857,30.012 37.198,30.353 U26.2@37.198,30.769
  Top Layer w0.3: C217.1@35.623,28.519 35.668,28.564 35.957,28.564 36.233,28.84 v1(36.233,28.876)
  Top Layer w0.4: C217.1@35.623,28.459 35.623,28.519 35.623,29.154 36.297,29.829 36.673,29.829 36.857,30.012
  Signal Layer 4 w0.5: v1(46.7,48.75) 46.707,48.757 68.068,48.757 v1(68.075,48.75)
  Bottom Layer w0.2: v5(70.475,37.15) 70.875,37.15 C210.2@70.9,37.125 ; C210.2@70.875,37.096 70.875,38.475
  Bottom Layer w0.5: v1@36.214,28.877 36.775,29.438 36.775,35.501 38.318,37.044 38.318,39.173 38.761,39.616 38.761,40.93 46.581,48.75 v1(46.7,48.75) ; v1(68.075,48.75) 68.3,48.75 69.85,47.2 69.85,43.425 70.875,42.4 70.875,38.475
  other v2: 70.475,37.15
  other v4: 70.475,37.15
VPP_DDR: C91.1 C252.2 C255.2 U17.B1 U17.R9 U26.7 | length 97.5
  Top Layer w0.21: U26.7@39.198,30.769 39.198,29.164 39.613,28.749 39.613,28.392
  Top Layer w0.3: v1(39.138,25.719) C91.1@39.748,25.719 ; 39.613,28.392 39.613,28.257 40.233,27.637 40.233,27.174 39.748,26.689 C91.1@39.748,25.869 ; v1(82.09,40.65) U17.B1@82.65,40.65 ; U17.R9@89.05,30.25 C252.2@90.07,30.25
  Top Layer w0.4: C252.2@90.24,30.395 91.04,30.395
  Top Layer w0.7: v1@89.994,24.519 91.04,25.565 91.04,30.395 ; v1(90.125,43.45) 91.89,43.45 92.725,42.615 92.725,32.055 91.09,30.42
  Signal Layer 4 w0.7: v1(39.138,25.719) 39.259,25.719 42.471,22.507 88.009,22.507 v1@90.008,24.505
  Bottom Layer w0.3: C255.2@81.254,40.851 81.455,40.65 v1(82.09,40.65)
  Bottom Layer w0.44: 80.604,41.321 81.095,40.83 81.275,40.83 C255.2@81.31,40.795
  Bottom Layer w0.6: 80.604,41.321 80.604,43.446 80.983,43.825 83.95,43.825 84.33,43.445 v1@90.125,43.445 ; v1(90.125,43.45) v1@90.126,43.451
  other v1: 90,24.525
VREF+: C248.2 C250.2 R269.2 U14.U2 | length 4.9
  Top Layer w0.075: v1@65.375,30.3 65.793,30.3 65.878,30.384 66.062,30.384 66.224,30.547 66.224,30.574 66.3,30.65 U14.U2@66.475,30.65
  Bottom Layer w0.2: v1@65.4,30.325 65.4,32.45 R269.2@65.55,32.6 ; v1(65.425,30.25) 65.506,30.25 65.781,30.525 65.875,30.525 C248.2@65.95,30.6 ; C248.2@65.955,30.605 65.96,30.6 66.565,30.6 C250.2@66.57,30.605
VTT_DDR: C40.2 C144.2 C145.2 C146.2 C160.2 C226.2 C239.2 C254.2 C256.2 C257.2 C258.2 C259.2 C261.2 C265.2 C266.2 R252.2 R253.2 R254.2 R255.2 R256.2 R257.2 R258.2 R259.2 R263.2 R264.2 R265.2 R266.2 R268.2 R271.2 R273.2 R275.2 R276.2 R277.2 R278.2 R279.2 R280.2 R281.2 R282.2 R283.2 R284.2 U26.44 | length 95.8
  Top Layer w0.21: 35.673,36.139 U26.44@36.228,36.139
  Top Layer w0.25: v6(30.6,35.612) 30.873,35.339 32.473,35.339 32.718,35.584 32.718,35.774 32.833,35.889 C40.2@32.903,35.889 ; C40.2@32.908,35.774 33.063,35.929 33.338,35.929 33.548,36.139 35.673,36.139
  Top Layer w0.5: v6(30.6,35.612) v6@30.6,36.335
  Signal Layer 4 w0.6: 29.774,35.613 29.774,36.336
  Signal Layer 4 w0.7: v6@30.599,36.336 29.774,36.336 28.643,36.336 27.608,35.301 26.236,35.301 25.282,36.255 25.282,43.871 31.098,49.687 74.213,49.687 80.859,43.041 88.986,43.041 91.051,40.976 v1@93.674,40.976
  other v1: 93.675,40.975
  other v6: 30.598,36.337
pads on no net: U14.G17 U14.K17 U14.N17 U14.P1 U14.P17 U14.T12 U17.P9 U17.T7 U37.A1 U37.A2 U37.A7 U37.A8 U37.A9 U37.A10 U37.A11 U37.A12 U37.A13 U37.A14 U37.B1 U37.B7 U37.B8 U37.B9 U37.B10 U37.B11 U37.B12 U37.B13 U37.B14 U37.C1 U37.C3 U37.C5 U37.C7 U37.C8 U37.C9 U37.C10 U37.C11 U37.C12 U37.C13 U37.C14 U37.D1 U37.D2 U37.D3 U37.D4 U37.D12 U37.D13 U37.D14 U37.E1 U37.E2 U37.E3 U37.E5 U37.E8 U37.E9 U37.E10 U37.E12 U37.E13 U37.E14 U37.F1 U37.F2 U37.F3 U37.F10 U37.F12 U37.F13 U37.F14 U37.G1 U37.G2 U37.G3 U37.G10 U37.G12 U37.G13 U37.G14 U37.H1 U37.H2 U37.H3 U37.H12 U37.H13 U37.H14 U37.J1 U37.J2 U37.J3 U37.J12 U37.J13 U37.J14 U37.K1 U37.K2 U37.K3 U37.K6 U37.K7 U37.K10 U37.K12 U37.K13 U37.K14 U37.L1 U37.L2 U37.L3 U37.L12 U37.L13 U37.L14 U37.M1 U37.M2 U37.M3 U37.M7 U37.M8 U37.M9 U37.M10 U37.M11 U37.M12 U37.M13 U37.M14 U37.N1 U37.N3 U37.N6 U37.N7 U37.N8 U37.N9 U37.N10 U37.N11 U37.N12 U37.N13 U37.N14 U37.P1 U37.P2 U37.P7 U37.P8 U37.P9 U37.P10 U37.P11 U37.P12 U37.P13 U37.P14
copper on no net: | length 0.4
  Signal Layer 1 w0.1: 73.712,22.092 73.715,22.095
  Signal Layer 2 w0.075: 69.22,45.77 69.225,45.775
  Signal Layer 4 w0.09: 54.67,69.65 54.673,69.647 ; 54.673,69.127 54.75,69.05
  Bottom Layer w0.09: 29.625,93.625 29.8,93.8

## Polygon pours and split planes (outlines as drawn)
5V_STLK on Signal Layer 4 "5V_STLK" (solid, pour order 297): 125,95.201 125,0.3 0,0.3 0,95.201
VDDGPU on Signal Layer 4 "VDDGPU" (solid, remove dead copper, pour order 272): 53.029,33.196 55.325,30.9 70.275,30.9 70.275,32.1 70.725,32.1 70.725,33.35 73.25,33.35 73.25,28.075 49.673,28.075 46.8,30.879 46.8,34.699 47.529,35.428 53.029,35.428
VDDCPU on Signal Layer 4 "VDDCPU" (solid, remove dead copper, pour order 292): 46.237,38.475 69.4,38.475 71.025,36.85 71.025,32.9 73.2,32.9 73.2,42.193 72.754,42.638 40.002,42.638 40.002,42.651 39.116,43.538 30.242,43.538 28.618,41.913 28.618,39.888 28.718,39.988 38.515,39.988 39.454,39.05 39.542,39.138 45.574,39.138
3V3 on Signal Layer 4 "3V3_L4" (solid, remove dead copper, pour order 294): 33.955,30.677 32.353,29.075 15.11,29.075 15.11,19.532 37.399,19.532 37.399,30.677
VDD_DDR on Signal Layer 4 "VDD_DDR" (solid, remove dead copper, pour order 293): 28.618,39.875 32.3,39.875 32.625,39.55 32.625,37.225 32.008,36.608 28.617,36.609 27.615,35.606 26.317,35.606 25.645,36.278 25.645,43.516 30.252,48.123 75.839,48.123 81.412,42.55 91.14,42.55 91.14,26.204 79.052,26.122 76.174,29 73.2,31.975 73.2,42.125 73.234,42.159 73.159,42.233 28.938,42.233 28.618,41.913
VDDCORE on Signal Layer 4 "VDDCORE" (solid, remove dead copper, pour order 291): 53.144,33.175 55.394,30.925 70.975,30.925 70.975,36.735 69.335,38.375 53.144,38.375
GND on Bottom Layer "GND" (solid, remove dead copper, pour order 257): 0,95 125,95 125,0 0,0
VTT_DDR on Bottom Layer "VTT_DDR_L06_P247" (solid, remove dead copper, pour order 247): 90.467,41.805 90.467,44.095 95.217,44.095 95.217,41.095 93.477,39.345 93.477,23.345 92.143,23.345 92.143,24.338 92.143,39.989 91.857,40.275 88.893,40.275 87.653,39.035 85.697,39.035 85.467,38.805 82.537,38.805 82.537,39.785 83.197,39.785 84.092,40.68 84.092,41.22 84.217,41.345 85.017,41.345 85.217,41.145 85.217,40.885 87.157,40.885 87.157,41.805
GND on Top Layer "GND_L01_P283" (solid, pour order 283): -0.345,95.136 125,95.136 125,-0.164 0.005,-0.164
VDDIO on Top Layer "VDDIO" (solid, pour order 280): 41.893,36.909 41.893,38.707 42.428,39.242 42.61,39.242 43.048,38.803 43.048,38.262 42.348,37.562 42.348,36.909
VDDCORE on Top Layer "VDDCORE_TOP" (solid, pour order 278): 51.905,42.834 54.787,39.952 54.787,33.725 54.792,33.72 53.338,33.72 52.793,34.265 52.793,38.966 52.42,39.339 50.773,39.339 46.413,39.339 46.403,42.834
NetL6_1 on Top Layer "NetL13_1" (solid, pour order 282): 44.273,32.002 44.736,31.539 45.998,31.539 45.998,29.239 45.996,29.237 44.699,29.237 44.699,30.861 44.273,31.287
3V3 on Top Layer "3V3" (solid, pour order 281): 23.785,26.687 23.96,26.512 30.308,26.512 31.61,27.814 31.61,28.662 23.986,28.662 23.785,28.462
VDDGPU on Top Layer "VDDGPU_TOP" (solid, pour order 279): 52.501,33.739 52.643,33.881 52.643,36.859 47.923,36.859 47.923,33.739
VDDCPU on Top Layer "VDDCPU_TOP" (solid, pour order 277): 28.71,41.984 28.71,40.137 29.233,39.614 33.648,39.614 33.643,39.619 33.643,41.984
5V_STLK on Top Layer "5V_VIN" (solid, pour order 259): 33.408,33.759 34.065,33.759 34.248,33.942 34.248,33.602 33.765,33.119 33.408,33.119
GND on Signal Layer 3 "GND" (solid, pour order 298): 125,95 125,0 0,0 0,95
VDDIO on Signal Layer 3 "VDDIO" (solid, remove dead copper, pour order 252): 69.775,35.95 70.025,36.2 70.025,36.9 70.8,36.9 70.8,33.9 70.525,33.9 70.525,26.35 53.129,26.35 51.952,27.527 51.952,29.784 53.344,31.176 63.125,31.176 63.125,34.2 68.275,34.2 68.275,34.3 69.275,34.3 69.275,35.95
1V8 on Signal Layer 3 "1V8_L04_P295" (solid, pour order 295): 66.275,34.3 71.55,34.3 71.55,27.275 73.9,27.275 86.65,27.275 86.65,52.875 76.525,52.875 76.525,49.35 39.4,49.35 39.4,39.55 66.275,39.55
GND on Signal Layer 2 "GND_L03_P299" (solid, pour order 299): -0.037,95 125,95 125,0 0.311,0
VDDIO on Signal Layer 2 "VDDIO_L03_P258" (solid, pour order 258): 70.675,37.35 67.95,37.35 67.95,33.35 70.675,33.35
GND on Signal Layer 1 "gnd" (solid, pour order 236): -0.171,95 125,95 125,0 0.002,0

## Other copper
Top Layer:
  rectangle net VDD_DDR: 26.553,31.939 29.523,33.739
Signal Layer 1:
  text "2" at 121.175,16.8 h1.2 r90
Signal Layer 2:
  text "3" at 121.175,18.05 h1.2 r90
Signal Layer 3:
  text "4" at 121.175,19.3 h1.2 r90
Signal Layer 4:
  text "5" at 121.175,20.55 h1.2 r90
Bottom Layer:
  text "6" at 121.175,21.8 h1.2 r90

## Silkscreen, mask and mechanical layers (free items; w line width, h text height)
Top Overlay:
  text "J" at 52.575,79.925 h20
Bottom Overlay:
  lines w0.1: 55.225,72.525 55.225,47.925 76.7,47.925 76.7,72.528 55.225,72.528 ; 69.675,44.8 70.025,44.45 ; 70.025,47.85 70.025,44.45 ; 70.375,44.8 70.025,44.45
  text "J" at 31.1,87.65 h15
Top Paste:
  text ".Layer_Name" at 27.423,-26.172 h3
  text ".GTP" at 69.118,-26.172 h3
Bottom Paste:
  text ".GBP" at 57.907,-26.196 h3
  text ".Layer_Name" at 99.221,-26.196 h3
Top Solder:
  text ".Layer_Name" at 27.423,-26.172 h3
  text ".GTS" at 69.118,-26.172 h3
Bottom Solder:
  text ".GBS" at 57.907,-26.196 h3
  text ".Layer_Name" at 99.221,-26.196 h3
M1-Board Shape:
  the board outline again, w0.1
M14-Top Assembly:
  text ".Layer_Name" at 27.423,-26.172 h3
  text ".GM14" at 69.118,-26.172 h3
M15-Bottom Assembly:
  text ".GM15" at 57.907,-26.196 h3
  text ".Layer_Name" at 99.221,-26.196 h3
Drill Drawing:
  drawing of 407 lines, arcs and shapes, not listed
  text "MINIMUN PARAMETERS" at 150.3,143.65 h3
  text "PCB SPECIFICATIONS :" at -1.425,142.95 h3
  text "A.   MATERIAL :" at -1.425,138.95 h3
  text "FR-4" at 37.075,138.95 h3
  text "TG-170" at 53.575,138.95 h3
  text "X  TG-150" at 71.825,138.95 h3
  text "TG-140" at 87.825,138.95 h3
  text "DEFAULT" at 150.3,138.15 h3
  text "B.   MATERIAL FAMILY :" at -1.425,135.95 h3
  text "N/A" at 37.075,135.95 h3
  text "C.   SOLDERMASK COLOR :" at -1.425,132.95 h3
  text "GREEN" at 37.075,132.95 h3
  text "X  BLUE" at 53.575,132.95 h3
  text "RED" at 71.825,132.95 h3
  text "BLACK" at 87.825,132.95 h3
  text "TRACKS : 0.100mm           / GAPS : 0.100mm" at 150.3,132.4 h3
  text "D.   SILKSCREEN COLOR :" at -1.425,129.95 h3
  text "X  WHITE" at 37.075,129.95 h3
  text "YELLOW" at 53.575,129.95 h3
  text "BLACK" at 71.825,129.95 h3
  text "E.   SURFACE FINISH :" at -1.425,126.95 h3
  text "X  ENIG" at 37.075,126.95 h3
  text "IMMERSION SILVER" at 53.575,126.95 h3
  text "IMMERSION TIN" at 87.825,126.95 h3
  text "UNDER MPU" at 150.3,125.9 h3
  text "HASL" at 37.075,123.95 h3
  text "HASL (PB-FREE)" at 53.575,123.95 h3
  text "GOLDEN FINGER" at 87.825,123.95 h3
  text "F.   IMPEDANCE CONTROL :" at -1.425,120.95 h3
  text "NO" at 37.075,120.95 h3
  text "X  YES  (SEE IMPEDANCE TABLE FOR DETAIL INFORMATION)" at 53.575,120.95 h3
  text "TRACKS : 0.075mm           / GAPS : 0.082mm" at 150.3,120.15 h3
  text "G.   THROUGH VIA :" at -1.425,117.95 h3
  text "PLUG THE VIAS WHICH ARE COVERED WITH SOLDERMASK ONE OR TWO SIDE." at 37.075,117.95 h3
  text "PLUG MATERIAL :" at 37.075,114.95 h3
  text "X  SOLDERMASK" at 62.575,114.95 h3
  text "NON-CONDUCTIVE EPOXY." at 87.825,114.95 h3
  text "UNDER DDR" at 150.3,113.9 h3
  text "H.   STACK-UP :" at -1.425,111.95 h3
  text "SEE LAYER STACK-UP SEQUENCE FOR OVERALL THICKNESS." at 37.075,111.95 h3
  text "TRACKS : 0.090mm           / GAPS : 0.090mm" at 150.3,108.15 h3
  text "Layer" at 135.6,101.625 h2
  text "Name" at 143.964,101.625 h2
  text "Material" at 160.132,101.625 h2
  text "Thickness" at 174.666,101.625 h2
  text "Constant" at 186.602,101.625 h2
  text "Board Layer Stack" at 197.654,101.625 h2
  text "Top Overlay" at 143.964,97.625 h2
  text "Top Solder" at 143.964,93.625 h2
  text "Solder Resist" at 160.132,93.625 h2
  text "0.025mm" at 174.666,93.625 h2
  text "3.5" at 186.602,93.625 h2
  text "1" at 135.6,89.625 h2
  text "Top Layer" at 143.964,89.625 h2
  text "0.046mm" at 174.666,89.625 h2
  text "Dielectric 1" at 143.964,85.625 h2
  text "0.071mm" at 174.666,85.625 h2
  text "4.21" at 186.602,85.625 h2
  text "2" at 135.598,81.625 h2
  text "Signal Layer 1" at 143.964,81.625 h2
  text "0.035mm" at 174.666,81.625 h2
  text "Dielectric 2" at 143.964,77.625 h2
  text "0.094mm" at 174.666,77.625 h2
  text "4.09" at 186.602,77.625 h2
  text "3" at 135.6,73.625 h2
  text "Signal Layer 2" at 143.964,73.625 h2
  text "0.023mm" at 174.666,73.625 h2
  text "Dielectric 3" at 143.964,69.625 h2
  text "0.865mm" at 174.666,69.625 h2
  text "4.68" at 186.602,69.625 h2
  text "4" at 135.6,65.625 h2
  text "Signal Layer 3" at 143.964,65.625 h2
  text "0.023mm" at 174.666,65.625 h2
  text "Dielectric 4" at 143.964,61.625 h2
  text "0.094mm" at 174.666,61.625 h2
  text "4.09" at 186.602,61.625 h2
  text "5" at 135.6,57.625 h2
  text "Signal Layer 4" at 143.964,57.625 h2
  text "0.035mm" at 174.666,57.625 h2
  text "Dielectric5" at 143.964,53.625 h2
  text "0.071mm" at 174.666,53.625 h2
  text "4.21" at 186.602,53.625 h2
  text "6" at 135.6,49.625 h2
  text "Bottom Layer" at 143.964,49.625 h2
  text "0.046mm" at 174.666,49.625 h2
  text "Bottom Solder" at 143.964,45.625 h2
  text "Solder Resist" at 160.132,45.625 h2
  text "0.025mm" at 174.666,45.625 h2
  text "3.5" at 186.602,45.625 h2
  text "Bottom Overlay" at 143.964,41.625 h2
  text "Symbol" at 136.016,-15.13 h2.4
  text "Count" at 145.405,-15.13 h2.4
  text "Hole Size" at 155.14,-15.13 h2.4
  text "Plated" at 173.374,-15.13 h2.4
  text "Hole Type" at 181.617,-15.13 h2.4
  text "Drill Layer Pair" at 193.617,-15.13 h2.4
  text "Via/Pad" at 216.346,-15.13 h2.4
  text "Pad Shape" at 226.178,-15.13 h2.4
  text "Template" at 239.023,-15.13 h2.4
  text "Hole Tolerance (+)" at 270.138,-15.13 h2.4
  text "Hole Tolerance (-)" at 290.198,-15.13 h2.4
  text "2" at 145.405,-19.267 h2
  text "0.500mm (19.69mil)" at 155.14,-19.267 h2
  text "PTH" at 173.374,-19.267 h2
  text "Round" at 181.617,-19.267 h2
  text "Top Layer - Bottom Layer" at 193.617,-19.267 h2
  text "Pad" at 216.346,-19.267 h2
  text "Rounded" at 226.178,-19.267 h2
  text "r100_130h50r100m105_135(Tol5-5)" at 239.023,-19.267 h2
  text "0.050mm (1.97mil)" at 270.138,-19.267 h2
  text "0.050mm (1.97mil)" at 290.198,-19.267 h2
  text "55" at 145.405,-23.405 h2
  text "0.350mm (13.78mil)" at 155.14,-23.405 h2
  text "PTH" at 173.374,-23.405 h2
  text "Round" at 181.617,-23.405 h2
  text "Top Layer - Bottom Layer" at 193.617,-23.405 h2
  text "Via" at 216.346,-23.405 h2
  text "Rounded" at 226.178,-23.405 h2
  text "v55h35m40mx40" at 239.023,-23.405 h2
  text "394" at 145.405,-27.542 h2
  text "0.200mm (7.87mil)" at 155.14,-27.542 h2
  text "PTH" at 173.374,-27.542 h2
  text "Round" at 181.617,-27.542 h2
  text "(Mixed)" at 193.617,-27.542 h2
  text "Via" at 216.346,-27.542 h2
  text "Rounded" at 226.178,-27.542 h2
  text "(Mixed)" at 239.023,-27.542 h2
  text "490" at 145.405,-31.68 h2
  text "0.100mm (3.94mil)" at 155.14,-31.68 h2
  text "PTH" at 173.374,-31.68 h2
  text "Round" at 181.617,-31.68 h2
  text "(Mixed)" at 193.617,-31.68 h2
  text "Via" at 216.346,-31.68 h2
  text "Rounded" at 226.178,-31.68 h2
  text "v26h10" at 239.023,-31.68 h2
  text "941 Total" at 145.405,-35.817 h2
M20-Top Sheet Box:
  circle w0.254: c105.427,-32.893 r1.3
  lines w0.254: 81.186,-31.493 89.978,-31.493 86.912,-27.956 cw(c88.716,-26.012) 88.956,-23.371 105.72,-23.371 104.958,-25.657 ; 84.5,-23.124 cw(c86.926,-24.094) 87.163,-21.492 ; 84.539,-23.091 80.193,-33.986 99.515,-33.986 ccw(c99.764,-31.252) 102.313,-32.272 ; 86.279,-27.026 91.701,-33.282 ; 86.533,-27.026 91.838,-33.147 ; 86.533,-26.772 91.838,-32.893 ; 86.631,-25.657 99.624,-25.657 ; 86.66,-26.645 91.965,-32.766 ; 86.787,-26.518 92.092,-32.639 ; 86.914,-26.391 92.219,-32.512 ; 87.041,-26.264 92.346,-32.385 ; 87.096,-24.312 92.401,-30.433 ; 87.164,-21.492 106.614,-21.492 102.314,-32.269 ; 87.168,-26.137 92.418,-32.195 ; 87.168,-25.883 92.473,-32.004 ; 87.168,-25.629 92.473,-31.75 ; 87.168,-24.74 92.473,-30.861 ; 87.295,-25.502 92.6,-31.623 ; 87.295,-25.121 92.6,-31.242 ; 88.667,-31.507 ccw(c88.772,-30.972) 89.069,-30.515 ; 89.753,-25.643 ccw(c89.727,-26.211) 89.397,-26.673 91.762,-29.401 cw(c89.958,-31.345) 90.691,-33.894 ; 96.034,-33.782 98.924,-25.403 ; 96.257,-33.732 99.126,-25.412 ; 96.384,-33.732 99.253,-25.412 ; 96.638,-33.732 99.507,-25.412 ; 96.892,-33.732 99.761,-25.412 ; 97.146,-33.732 100.015,-25.412 ; 97.4,-33.732 100.269,-25.412 ; 97.654,-33.732 100.523,-25.412 ; 97.908,-33.732 100.777,-25.412 ; 98.162,-33.732 101.031,-25.412 ; 98.37,-33.782 101.26,-25.403 ; 101.26,-25.657 104.952,-25.657 ; 104.284,-25.654 105.046,-23.368 ; 104.45,-25.657 105.212,-23.371 ; 104.704,-25.657 105.466,-23.371
  lines w0.3: 18.423,-32.872 78.423,-32.872 ; 18.423,-27.872 78.423,-27.872 ; 18.423,-22.872 78.423,-22.872 ; 58.423,-37.872 58.423,-22.872 ; 78.423,-37.872 78.423,-17.872 ; 96.034,-33.782 98.37,-33.782 ; 18.423,-37.872 108.423,-37.872 108.423,-17.872 18.423,-17.872 18.423,-37.872
M21-Bottom Sheet Box:
  circle w0.254: c21.598,-32.885 r1.3
  lines w0.254: 21.559,-23.363 22.321,-25.649 ; 21.813,-23.363 22.575,-25.649 ; 21.979,-23.36 22.741,-25.646 ; 22.067,-25.649 21.305,-23.363 38.069,-23.363 cw(c38.309,-26.004) 40.113,-27.948 37.047,-31.485 45.839,-31.485 ; 22.073,-25.649 25.766,-25.649 ; 24.711,-32.261 20.412,-21.484 39.861,-21.484 ; 24.712,-32.264 ccw(c27.261,-31.244) 27.51,-33.978 46.832,-33.978 42.486,-23.083 ; 25.766,-25.395 28.655,-33.774 ; 25.994,-25.404 28.863,-33.724 ; 26.248,-25.404 29.117,-33.724 ; 26.502,-25.404 29.371,-33.724 ; 26.756,-25.404 29.625,-33.724 ; 27.01,-25.404 29.879,-33.724 ; 27.264,-25.404 30.133,-33.724 ; 27.401,-25.649 40.394,-25.649 ; 27.518,-25.404 30.387,-33.724 ; 27.772,-25.404 30.641,-33.724 ; 27.899,-25.404 30.768,-33.724 ; 28.101,-25.395 30.991,-33.774 ; 34.425,-31.615 39.73,-25.494 ; 34.425,-31.234 39.73,-25.113 ; 34.552,-31.996 39.857,-25.875 ; 34.552,-31.742 39.857,-25.621 ; 34.552,-30.853 39.857,-24.732 ; 34.607,-32.187 39.857,-26.129 ; 34.625,-30.425 39.93,-24.304 ; 34.679,-32.377 39.984,-26.256 ; 34.806,-32.504 40.111,-26.383 ; 34.933,-32.631 40.238,-26.51 ; 35.06,-32.758 40.365,-26.637 ; 35.187,-33.139 40.492,-27.018 ; 35.187,-32.885 40.492,-26.764 ; 35.324,-33.274 40.746,-27.018 ; 36.335,-33.886 cw(c37.067,-31.337) 35.264,-29.394 37.628,-26.665 ccw(c37.298,-26.203) 37.272,-25.635 ; 37.956,-30.507 ccw(c38.254,-30.964) 38.359,-31.499 ; 39.863,-21.484 cw(c40.099,-24.086) 42.525,-23.116
  lines w0.3: 28.655,-33.774 30.991,-33.774 ; 48.416,-37.864 48.416,-17.864 ; 48.416,-32.864 108.416,-32.864 ; 48.416,-27.864 108.416,-27.864 ; 48.416,-22.864 108.416,-22.864 ; 68.416,-37.864 68.416,-22.864 ; 18.416,-37.864 18.416,-17.864 108.416,-17.864 108.416,-37.864 18.416,-37.864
